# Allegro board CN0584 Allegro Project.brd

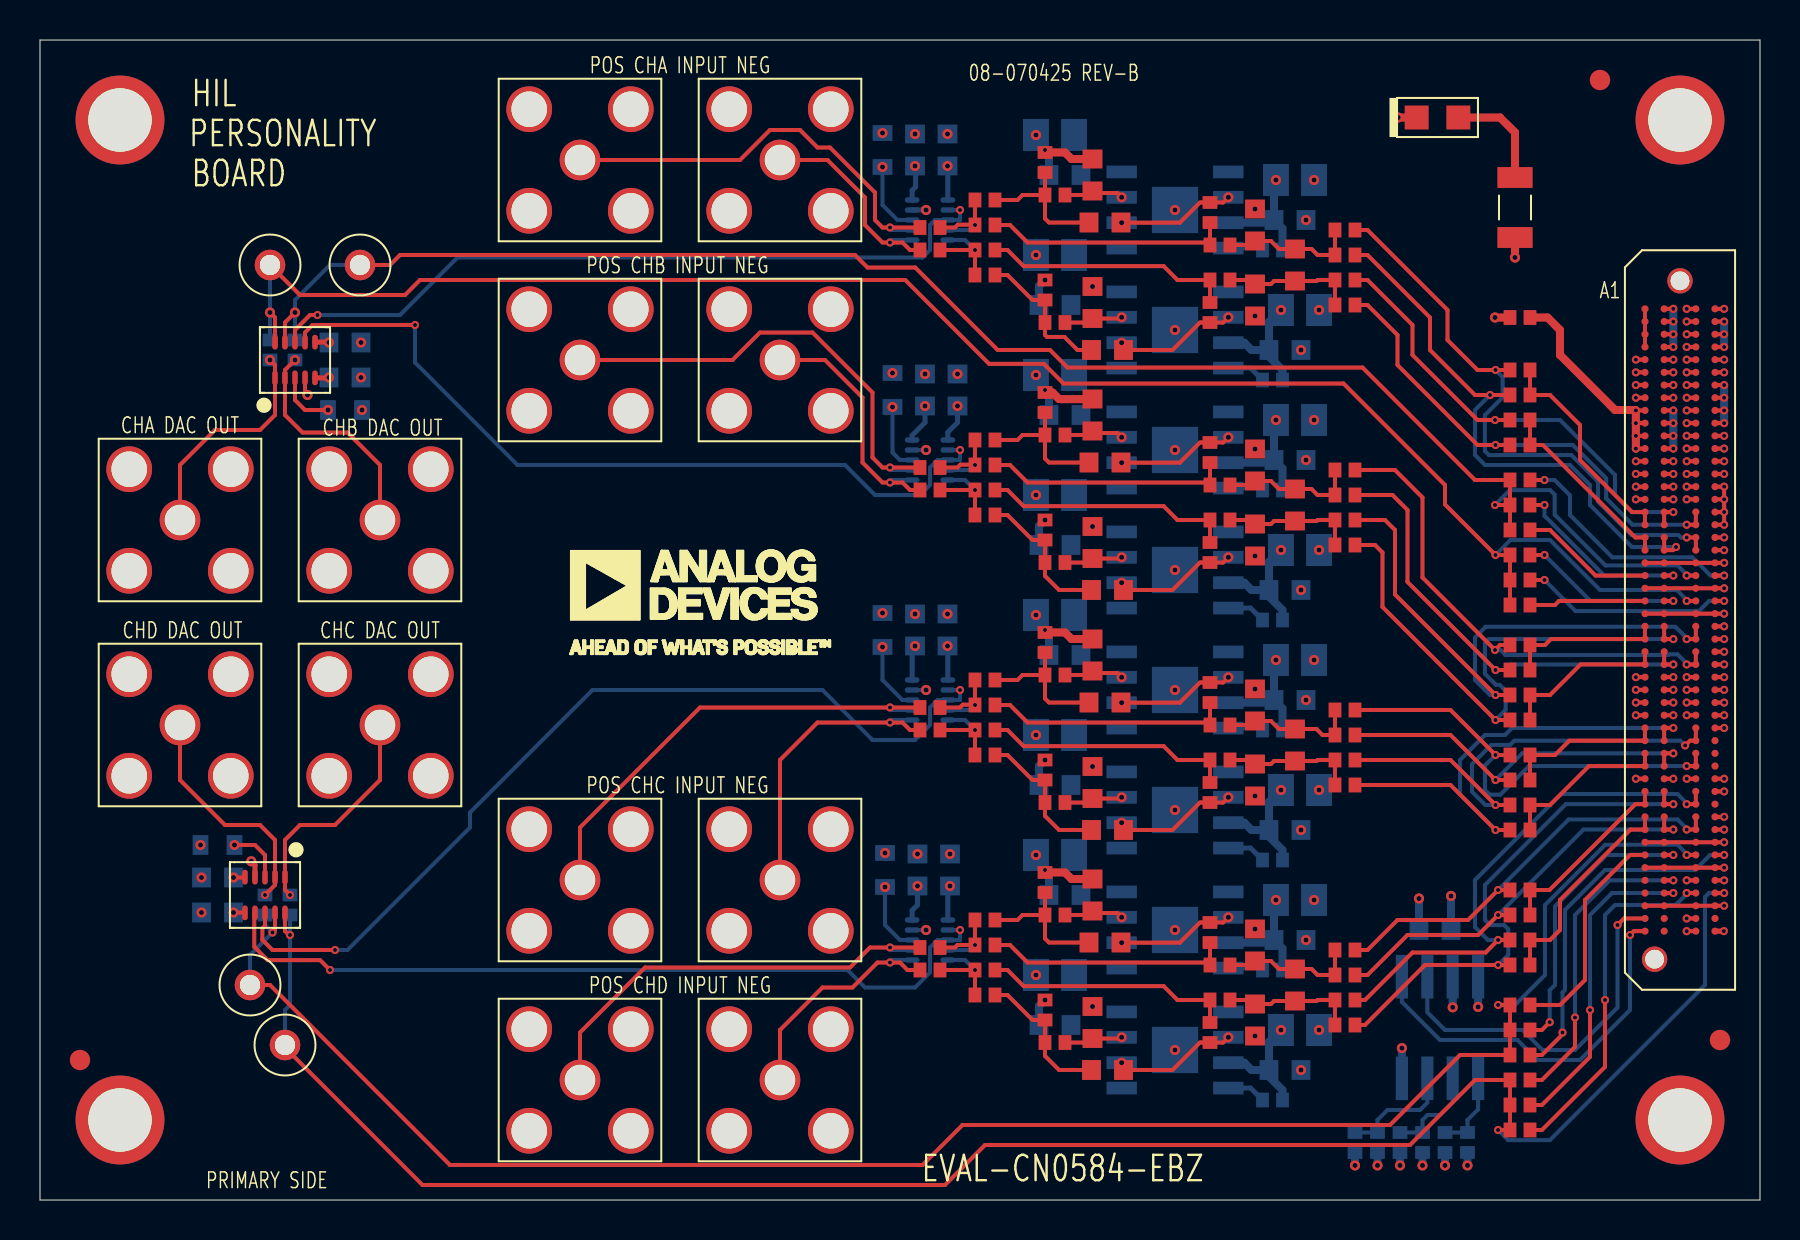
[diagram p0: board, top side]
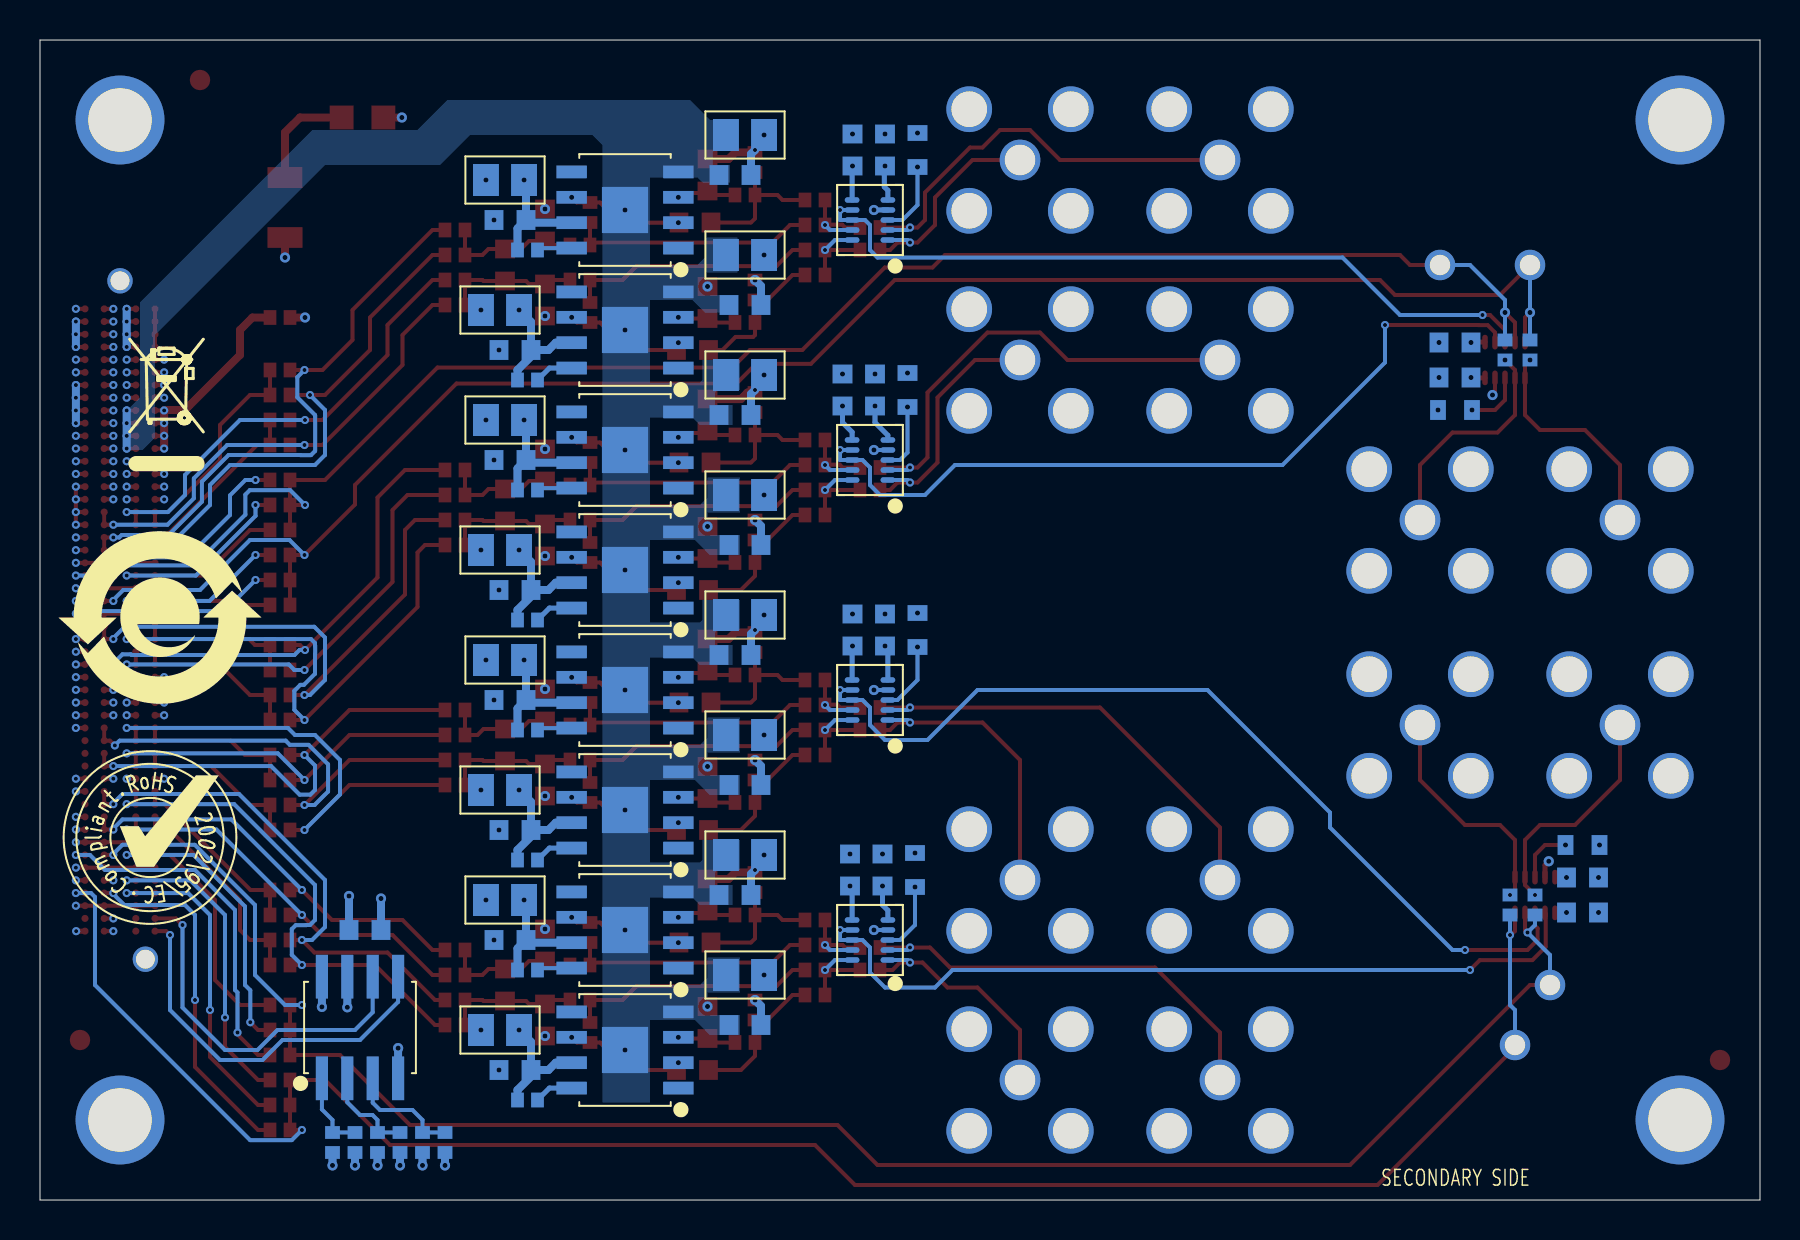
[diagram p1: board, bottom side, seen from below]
Outline 86 x 58 mm; copper layers: TOP, LAYER_2, LAYER_3, LAYER_4, LAYER_5, BOTTOM. Coordinates in mm from the lower left corner of the outline.
Outline path: 0,58 0,0 86,0 86,58 0,58

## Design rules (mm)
constraint set DEFAULT: 

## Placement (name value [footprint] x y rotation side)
C1  0.1uF  [C0603]  69.75 13.5 0 bottom
C1A  0.1uF  [C0603]  43.75 52.5 270 bottom
C1B  0.1uF  [C0603]  44.25 40.5 270 bottom
C1C  0.1uF  [C0603]  43.75 28.5 270 bottom
C1D  0.1uF  [C0603]  43.88 16.5 270 bottom
C2  0.1uF  [C0603]  8.88 16.12 0 bottom
C2A  0.1uF  [C0603]  45.38 52.5 270 bottom
C2B  0.1uF  [C0603]  45.88 40.5 270 bottom
C2C  0.1uF  [C0603]  45.38 28.5 270 bottom
C2D  0.1uF  [C0603]  45.5 16.5 270 bottom
C3  0.1uF  [C0603]  15.25 41.12 180 bottom
C3A  0.47uF  [C0603]  53.38 42.5 180 top
C3B  0.47uF  [C0603]  53.38 30.5 180 top
C3C  0.47uF  [C0603]  53.38 18.5 180 top
C3D  0.47uF  [C0603]  53.38 6.5 180 top
C4  0.1uF  [C0603]  15.25 42.88 180 bottom
C4A  0.47uF  [C0603]  53.25 48.88 180 top
C4B  0.47uF  [C0603]  53.25 36.88 180 top
C4C  0.47uF  [C0603]  53.25 24.88 180 top
C4D  0.47uF  [C0603]  53.25 12.88 180 top
C5  0.1uF  [C0603]  8.88 14.38 0 bottom
C5A  0.47uF  [C0603]  52.62 44.88 270 top
C5B  0.47uF  [C0603]  52.62 32.88 270 top
C5C  0.47uF  [C0603]  52.62 20.88 270 top
C5D  0.47uF  [C0603]  52.62 8.88 270 top
C6A  0.47uF  [C0603]  52.62 51.25 270 top
C6B  0.47uF  [C0603]  52.62 39.25 270 top
C6C  0.47uF  [C0603]  52.62 27.25 270 top
C6D  0.47uF  [C0603]  52.62 15.25 270 top
C7A  4.7uF  [C0805H53]  62.75 51 180 bottom
C7B  4.7uF  [C0805H53]  62.75 39 180 bottom
C7C  4.7uF  [C0805H53]  62.75 27 180 bottom
C7D  4.7uF  [C0805H53]  63 8.5 180 bottom
C8A  4.7uF  [C0805H53]  63 44.5 180 bottom
C8B  4.7uF  [C0805H53]  63 32.5 180 bottom
C8C  4.7uF  [C0805H53]  63 20.5 180 bottom
C8D  4.7uF  [C0805H53]  62.75 15 180 bottom
C9A  0.1uF  [C0603]  62.5 49 180 bottom
C9B  0.1uF  [C0603]  62.5 37 180 bottom
C9C  0.1uF  [C0603]  62.25 18.5 180 bottom
C9D  0.1uF  [C0603]  62.5 13 180 bottom
C10A  0.1uF  [C0603]  62.25 42.5 180 bottom
C10B  0.1uF  [C0603]  62.25 30.5 180 bottom
C10C  0.1uF  [C0603]  62.5 25 180 bottom
C10D  0.1uF  [C0603]  62.25 6.5 180 bottom
C11A  0.1uF  [C0603]  51.25 51.25 0 bottom
C11B  0.1uF  [C0603]  51.25 39.25 0 bottom
C11C  0.1uF  [C0603]  51.25 27.25 0 bottom
C11D  0.1uF  [C0603]  50.75 8.75 0 bottom
C12A  0.1uF  [C0603]  50.75 44.75 0 bottom
C12B  0.1uF  [C0603]  50.75 32.75 0 bottom
C12C  0.1uF  [C0603]  50.75 20.75 0 bottom
C12D  0.1uF  [C0603]  51.25 15.25 0 bottom
C13A  4.7uF  [C0805H53]  50.75 47.25 0 bottom
C13B  4.7uF  [C0805H53]  50.75 41.25 0 bottom
C13C  4.7uF  [C0805H53]  50.75 23.25 0 bottom
C13D  4.7uF  [C0805H53]  50.75 11.25 0 bottom
C14A  4.7uF  [C0805H53]  50.75 53.25 0 bottom
C14B  4.7uF  [C0805H53]  50.75 35.25 0 bottom
C14C  4.7uF  [C0805H53]  50.75 29.25 0 bottom
C14D  4.7uF  [C0805H53]  50.75 17.25 0 bottom
C15A  0.47uF  [C0603]  60.75 45 90 top
C15B  0.47uF  [C0603]  60.75 33 90 top
C15C  0.47uF  [C0603]  60.75 21 90 top
C15D  0.47uF  [C0603]  60.75 9 90 top
C16A  0.47uF  [C0603]  60.75 48.75 90 top
C16B  0.47uF  [C0603]  60.75 36.75 90 top
C16C  0.47uF  [C0603]  60.75 24.75 90 top
C16D  0.47uF  [C0603]  60.75 12.75 90 top
C17A  0.47uF  [C0603]  62.75 46.75 270 top
C17B  0.47uF  [C0603]  62.75 34.75 270 top
C17C  0.47uF  [C0603]  62.75 22.75 270 top
C17D  0.47uF  [C0603]  62.75 10.75 270 top
DS1  SML-LXT0805GW-TR  [LXT0805]  69.88 54.12 0 top
J1  901-144-8RFX  [CNTHSMASQ276H391]  27 52 0 top
J2  901-144-8RFX  [CNTHSMASQ276H391]  37 52 0 top
J3  901-144-8RFX  [CNTHSMASQ276H391]  27 42 0 top
J4  901-144-8RFX  [CNTHSMASQ276H391]  37 42 0 top
J5  901-144-8RFX  [CNTHSMASQ276H391]  27 16 0 top
J6  901-144-8RFX  [CNTHSMASQ276H391]  37 16 0 top
J7  901-144-8RFX  [CNTHSMASQ276H391]  27 6 0 top
J8  901-144-8RFX  [CNTHSMASQ276H391]  37 6 0 top
J9  901-144-8RFX  [CNTHSMASQ276H391]  7 34 0 top
J10  901-144-8RFX  [CNTHSMASQ276H391]  17 34 0 top
J11  901-144-8RFX  [CNTHSMASQ276H391]  17 23.75 0 top
J12  901-144-8RFX  [CNTHSMASQ276H391]  7 23.75 0 top
NOREF  -  []  26.5 26 0 top
NOREF#2  -  [unnamed#2]  2 7 0 top
NOREF#3  -  []  43 74 0 top
NOREF#4  -  []  86 58 180 top
NOREF#5  -  [unnamed#2]  4 54 0 top
NOREF#6  -  []  -67.2 -72.2 0 top
NOREF#7  -  []  -67.2 -72.2 0 top
NOREF#8  -  []  0 58 270 top
NOREF#9  -  [unnamed#2]  4 4 0 top
NOREF#10  -  []  249.66 215.46 0 top
NOREF#11  -  []  16.62 327.21 0 top
NOREF#12  -  []  0 0 0 top
NOREF#13  -  [unnamed#2]  82 54 0 top
NOREF#14  -  [unnamed#2]  84 8 0 top
NOREF#15  -  []  259.19 222.44 0 top
NOREF#16  -  []  86 0 90 top
NOREF#17  -  [unnamed#2]  82 4 0 top
NOREF#18  -  [unnamed#2]  78 56 0 top
NOREF#19  -  []  -67.2 -72.2 0 top
NOREF#20  -  []  80.5 18.12 180 bottom
NOREF#21  -  []  79.88 36.5 180 bottom
NOREF#22  -  []  80 29.12 180 bottom
P1  ADM6-50-01.5-L-4-2-A-TR  [CNSMMHDR4X50L1436W197H161]  82 29 270 top
R1  560  [R1206]  73.75 49.62 90 top
R1A  34K  [R0603]  42.12 52.5 90 bottom
R1B  34K  [R0603]  42.62 40.5 90 bottom
R1C  34K  [R0603]  42.12 28.5 90 bottom
R1D  34K  [R0603]  42.25 16.5 90 bottom
R2  0  [R0402]  74 44.12 0 top
R2A  0  [R0402]  44.5 47.5 0 top
R2B  0  [R0402]  44.5 35.5 0 top
R2C  0  [R0402]  44.5 23.5 0 top
R2D  0  [R0402]  44.5 11.5 0 top
R3  0  [R0402]  70.25 2.88 90 bottom
R3A  0  [R0402]  44.5 48.62 0 top
R3B  0  [R0402]  44.5 36.62 0 top
R3C  0  [R0402]  44.5 24.62 0 top
R3D  0  [R0402]  44.5 12.62 0 top
R4  10K  [R0402]  71.38 2.88 90 bottom
R4A  1K  [R0402]  47.25 46.25 0 top
R4B  1K  [R0402]  47.25 34.25 0 top
R4C  1K  [R0402]  47.25 22.25 0 top
R4D  1K  [R0402]  47.25 10.25 0 top
R5  0  [R0402]  68 2.88 90 bottom
R5A  1K  [R0402]  47.25 50 180 top
R5B  1K  [R0402]  47.25 38 180 top
R5C  1K  [R0402]  47.25 26 180 top
R5D  1K  [R0402]  47.25 14 180 top
R6  10K  [R0402]  69.12 2.88 90 bottom
R6A  10K  [R0402]  50.25 45.5 270 top
R6B  10K  [R0402]  50.25 33.5 270 top
R6C  10K  [R0402]  50.25 21.5 270 top
R6D  10K  [R0402]  50.25 9.5 270 top
R7  0  [R0402]  65.75 2.88 90 bottom
R7A  10K  [R0402]  50.25 51.88 270 top
R7B  10K  [R0402]  50.25 39.88 270 top
R7C  10K  [R0402]  50.25 27.88 270 top
R7D  10K  [R0402]  50.25 15.88 270 top
R8  10K  [R0402]  66.88 2.88 90 bottom
R8A  0  [R0402]  50.75 43.88 0 top
R8B  0  [R0402]  50.75 31.88 0 top
R8C  0  [R0402]  50.75 19.88 0 top
R8D  0  [R0402]  50.75 7.88 0 top
R9  0  [R0402]  74 31 0 top
R9A  0  [R0402]  50.75 50.25 0 top
R9B  0  [R0402]  50.75 38.25 0 top
R9C  0  [R0402]  50.75 26.25 0 top
R9D  0  [R0402]  50.75 14.25 0 top
R10  0  [R0402]  74 29.75 0 top
R10A  0  [R0402]  47.25 47.5 0 top
R10B  0  [R0402]  47.25 35.5 0 top
R10C  0  [R0402]  47.25 23.5 0 top
R10D  0  [R0402]  47.25 11.5 0 top
R11  0  [R0402]  74 32.25 0 top
R11A  0  [R0402]  47.25 48.75 0 top
R11B  0  [R0402]  47.25 36.75 0 top
R11C  0  [R0402]  47.25 24.75 0 top
R11D  0  [R0402]  47.25 12.75 0 top
R12  0  [R0402]  74 36 0 top
R12A  0  [R0402]  61.62 47.5 180 bottom
R12B  0  [R0402]  61.62 35.5 180 bottom
R12C  0  [R0402]  61.62 23.5 180 bottom
R12D  0  [R0402]  61.62 11.5 180 bottom
R13  0  [R0402]  74 34.75 0 top
R13A  0  [R0402]  61.62 41 180 bottom
R13B  0  [R0402]  61.62 29 180 bottom
R13C  0  [R0402]  61.62 17 180 bottom
R13D  0  [R0402]  61.62 5 180 bottom
R14  0  [R0402]  74 33.5 0 top
R14A  0  [R0402]  58.5 44.38 270 top
R14B  0  [R0402]  58.5 32.38 270 top
R14C  0  [R0402]  58.5 20.38 270 top
R14D  0  [R0402]  58.5 8.38 270 top
R15  0  [R0402]  74 6 0 top
R15A  0  [R0402]  58.5 49.38 270 top
R15B  0  [R0402]  58.5 37.38 270 top
R15C  0  [R0402]  58.5 25.38 270 top
R15D  0  [R0402]  58.5 13.38 270 top
R16  0  [R0402]  74 3.5 0 top
R16A  0  [R0402]  59 46 180 top
R16B  0  [R0402]  59 34 180 top
R16C  0  [R0402]  59 22 180 top
R16D  0  [R0402]  59 10 180 top
R17  0  [R0402]  74 4.75 0 top
R17A  0  [R0402]  59 47.75 180 top
R17B  0  [R0402]  59 35.75 180 top
R17C  0  [R0402]  59 23.75 180 top
R17D  0  [R0402]  59 11.75 180 top
R18  0  [R0402]  74 7.25 0 top
R18A  0  [R0402]  65.25 46 180 top
R18B  0  [R0402]  65.25 32.75 180 top
R18C  0  [R0402]  65.25 20.75 180 top
R18D  0  [R0402]  65.25 8.75 180 top
R19  0  [R0402]  74 8.5 0 top
R19A  0  [R0402]  65.25 44.75 180 top
R19B  0  [R0402]  65.25 34 180 top
R19C  0  [R0402]  65.25 22 180 top
R19D  0  [R0402]  65.25 10 180 top
R20  0  [R0402]  74 9.75 0 top
R20A  0  [R0402]  65.25 47.25 180 top
R20B  0  [R0402]  65.25 35.25 180 top
R20C  0  [R0402]  65.25 23.25 180 top
R20D  0  [R0402]  65.25 11.25 180 top
R21  34K  [R0603]  8.88 17.75 180 bottom
R21A  0  [R0402]  65.25 48.5 180 top
R21B  0  [R0402]  65.25 36.5 180 top
R21C  0  [R0402]  65.25 24.5 180 top
R21D  0  [R0402]  65.25 12.5 180 top
R22  34K  [R0603]  15.25 39.5 0 bottom
R22A  0  [R0402]  74 39 180 top
R22B  0  [R0402]  74 24 180 top
R22C  0  [R0402]  74 18.5 180 top
R22D  0  [R0402]  74 11.75 180 top
R23  0  [R0402]  11.5 42.5 90 bottom
R23A  0  [R0402]  74 37.75 180 top
R23B  0  [R0402]  74 25.25 180 top
R23C  0  [R0402]  74 19.75 180 top
R23D  0  [R0402]  74 13 180 top
R24  0  [R0402]  12.5 14.75 270 bottom
R24A  0  [R0402]  74 40.25 180 top
R24B  0  [R0402]  74 26.5 180 top
R24C  0  [R0402]  74 21 180 top
R24D  0  [R0402]  74 14.25 180 top
R25  0  [R0402]  12.75 42.5 90 bottom
R25A  0  [R0402]  74 41.5 180 top
R25B  0  [R0402]  74 27.75 180 top
R25C  0  [R0402]  74 22.25 180 top
R25D  0  [R0402]  74 15.5 180 top
R26  0  [R0402]  11.25 14.75 270 bottom
TP1  BLK  [CNKEY5001TP]  11.5 46.75 90 top
TP2  BLK  [CNKEY5001TP]  16 46.75 90 top
TP3  BLK  [CNKEY5001TP]  12.25 7.75 270 top
TP4  BLK  [CNKEY5001TP]  10.5 10.75 270 top
U1  M24C02-RMN6TP  [SO8]  70 8.62 180 bottom
U1A  ADG5421FBCPZ-RL7  [DFN10_3X2]  44.5 49 90 bottom
U1B  ADG5421FBCPZ-RL7  [DFN10_3X2]  44.5 37 90 bottom
U1C  ADG5421FBCPZ-RL7  [DFN10_3X2]  44.5 25 90 bottom
U1D  ADG5421FBCPZ-RL7  [DFN10_3X2]  44.5 13 90 bottom
U2  ADG5421FBCPZ-RL7  [DFN10_3X2]  12.75 42 0 top
U2A  ADA4898-1YRDZ  [SO8NB-PAD2_3X2_3]  56.75 49.5 90 bottom
U2B  ADA4898-1YRDZ  [SO8NB-PAD2_3X2_3]  56.75 37.5 90 bottom
U2C  ADA4898-1YRDZ  [SO8NB-PAD2_3X2_3]  56.75 25.5 90 bottom
U2D  ADA4898-1YRDZ  [SO8NB-PAD2_3X2_3]  56.75 13.5 90 bottom
U3  ADG5421FBCPZ-RL7  [DFN10_3X2]  11.25 15.25 180 top
U3A  ADA4898-1YRDZ  [SO8NB-PAD2_3X2_3]  56.75 43.5 90 bottom
U3B  ADA4898-1YRDZ  [SO8NB-PAD2_3X2_3]  56.75 31.5 90 bottom
U3C  ADA4898-1YRDZ  [SO8NB-PAD2_3X2_3]  56.75 19.5 90 bottom
U3D  ADA4898-1YRDZ  [SO8NB-PAD2_3X2_3]  56.75 7.5 90 bottom

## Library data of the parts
C1 C1A C1B C1C C1D C2 C2A C2B C2C C2D C3-C5 C9A C9B C9C C9D C10A C10B C10C C10D C11A C11B C11C C11D C12A C12B C12C C12D = CAP: User Part Number: UPN; Tolerance: 10; alternate symbols: (C0603L); part number: CAP_SM-0.1UF,50V,10,E011865,C0603; tolerance: 10
C3A C3B C3C C3D C4A C4B C4C C4D C5A C5B C5C C5D C6A C6B C6C C6D C15A C15B C15C C15D C16A C16B C16C C16D C17A C17B C17C C17D = CAP: User Part Number: UPN; Tolerance: 10; alternate symbols: (C0603L); part number: CAP_SM-0.47UF,16V,10,E012085,C0603; tolerance: 10
C7A C7B C7C C7D C8A C8B C8C C8D C13A C13B C13C C13D C14A C14B C14C C14D = CAP: Tolerance: 10; User Part Number: UPN; alternate symbols: (); part number: CAP_SM-4.7UF,50V,10,E028468,C0805H53; tolerance: 10
DS1 = DIOLED: Tolerance: N/A; User Part Number: UPN; alternate symbols: (); part number: DIOLED_SM-SML-LXT0805GW-TR,N/A,N/A,E005318,LXT0805; tolerance: N/A
J1-J12 = CNBNC5P: Tolerance: N/A; User Part Number: UPN; alternate symbols: (); part number: CNBNC5P_TH-901-144-8RFX,E013428,CNTHSMASQ276H391; tolerance: N/A
P1 = CN200P_ABCD: User Part Number: UPN; Tolerance: N/A; alternate symbols: (); part number: CN200P_ABCD_SM-ADM6-50-01.5-L-4-2-A-TR,E056353,CNSMMHDR4X50L1436W197H161; tolerance: N/A
R1 = RES: User Part Number: UPN; Tolerance: 1; alternate symbols: (R1206L); part number: RES_SM-560,E012728,1/4W,1,R1206; tolerance: 1
R1A R1B R1C R1D R21 R22 = RES: User Part Number: UPN; Tolerance: 1; alternate symbols: (R0603L); part number: RES_SM-34K,E003688,1/10W,1,R0603; tolerance: 1
R2 R2A R2B R2C R2D R3 R3A R3B R3C R3D R5 R7 R8A R8B R8C R8D R9 R9A R9B R9C R9D R10 R10A R10B R10C R10D R11 R11A R11B R11C R11D R12 R12A R12B R12C R12D R13 R13A R13B R13C R13D R14 R14A R14B R14C R14D R15 R15A R15B R15C R15D R16 R16A R16B R16C R16D R17 R17A R17B R17C R17D R18 R18A R18B R18C R18D R19 R19A R19B R19C R19D R20 R20A R20B R20C R20D R21A R21B R21C R21D R22A R22B R22C R22D R23 R23A R23B R23C R23D R24 R24A R24B R24C R24D R25 R25A R25B R25C R25D R26 = RES: User Part Number: UPN; Tolerance: JUMPER; alternate symbols: (R0402L,R0402L_ALT); part number: RES_SM-0,E003438,1/10W,JUMPER,R0402; tolerance: JUMPER
R4 R6 R6A R6B R6C R6D R7A R7B R7C R7D R8 = RES: User Part Number: UPN; Tolerance: 1; alternate symbols: (R0402L,R0402L_ALT); part number: RES_SM-10K,E003751,1/10W,1,R0402; tolerance: 1
R4A R4B R4C R4D R5A R5B R5C R5D = RES: User Part Number: UPN; Tolerance: 5; alternate symbols: (R0402L); part number: RES_SM-1K,E020936,1/16W,5,R0402; tolerance: 5
TP1-TP4 = CNTP1P: Tolerance: N/A; User Part Number: UPN; alternate symbols: (); part number: CNTP1P_TH-BLK,E005347,CNKEY5001TP; tolerance: N/A
U1 = ICM24CXX: Tolerance: N/A; User Part Number: UPN; alternate symbols: (); part number: ICM24CXX_SM-M24C02-RMN6TP,E018349,SO8; tolerance: N/A
U1A U1B U1C U1D U2 U3 = ADG5421F: User Part Number: UPN; Tolerance: N/A; alternate symbols: (); part number: ADG5421F_SM-ADG5421FBCPZ-RL7,E033675,DFN10_3X2; tolerance: N/A
U2A U2B U2C U2D U3A U3B U3C U3D = ADA4898: Tolerance: N/A; User Part Number: UPN; alternate symbols: (); part number: ADA4898_SM-ADA4898-1YRDZ,E010180,SO8NB-PAD2_3X2_3; tolerance: N/A

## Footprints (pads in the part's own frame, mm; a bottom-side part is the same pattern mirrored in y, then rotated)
C0603
  rect 0.94x0.991 smd: 1(-0.8,0) 2(0.8,0)
C0805H53
  rect 1.295x1.6 smd: 1(-0.953,0) 2(0.953,0)
CNKEY5001TP
  round 1.524 hole 1.016: 1(0,0)
CNSMMHDR4X50L1436W197H161
  round 1.27 hole 0.94 unplated: (-16.96,0) (16.96,-1.27)
  round 0.356 smd: A1(-15.557,-1.75) A2(-14.922,-1.75) A3(-14.287,-1.75) A4(-13.652,-1.75) A5(-13.018,-1.75) A6(-12.383,-1.75) A7(-11.748,-1.75) A8(-11.113,-1.75) A9(-10.477,-1.75) A10(-9.842,-1.75) A11(-9.207,-1.75) A12(-8.572,-1.75) A13(-7.938,-1.75) A14(-7.303,-1.75) A15(-6.668,-1.75) A16(-6.032,-1.75) A17(-5.397,-1.75) A18(-4.763,-1.75) A19(-4.128,-1.75) A20(-3.493,-1.75) A21(-2.857,-1.75) A22(-2.223,-1.75) A23(-1.587,-1.75) A24(-0.953,-1.75) A25(-0.318,-1.75) A26(0.318,-1.75) A27(0.953,-1.75) A28(1.587,-1.75) A29(2.223,-1.75) A30(2.857,-1.75) A31(3.493,-1.75) A32(4.128,-1.75) A33(4.763,-1.75) A34(5.397,-1.75) A35(6.032,-1.75) A36(6.668,-1.75) A37(7.303,-1.75) A38(7.938,-1.75) A39(8.572,-1.75) A40(9.207,-1.75) A41(9.842,-1.75) A42(10.477,-1.75) A43(11.113,-1.75) A44(11.748,-1.75) A45(12.383,-1.75) A46(13.018,-1.75) A47(13.652,-1.75) A48(14.287,-1.75) A49(14.922,-1.75) A50(15.557,-1.75) B1(-15.557,-0.79) B2(-14.922,-0.79) B3(-14.287,-0.79) B4(-13.652,-0.79) B5(-13.018,-0.79) B6(-12.383,-0.79) B7(-11.748,-0.79) B8(-11.113,-0.79) B9(-10.477,-0.79) B10(-9.842,-0.79) B11(-9.207,-0.79) B12(-8.572,-0.79) B13(-7.938,-0.79) B14(-7.303,-0.79) B15(-6.668,-0.79) B16(-6.032,-0.79) B17(-5.397,-0.79) B18(-4.763,-0.79) B19(-4.128,-0.79) B20(-3.493,-0.79) B21(-2.857,-0.79) B22(-2.223,-0.79) B23(-1.587,-0.79) B24(-0.953,-0.79) B25(-0.318,-0.79) B26(0.318,-0.79) B27(0.953,-0.79) B28(1.587,-0.79) B29(2.223,-0.79) B30(2.857,-0.79) B31(3.493,-0.79) B32(4.128,-0.79) B33(4.763,-0.79) B34(5.397,-0.79) B35(6.032,-0.79) B36(6.668,-0.79) B37(7.303,-0.79) B38(7.938,-0.79) B39(8.572,-0.79) B40(9.207,-0.79) B41(9.842,-0.79) B42(10.477,-0.79) B43(11.113,-0.79) B44(11.748,-0.79) B45(12.383,-0.79) B46(13.018,-0.79) B47(13.652,-0.79) B48(14.287,-0.79) B49(14.922,-0.79) B50(15.557,-0.79) C1(-15.557,0.79) C2(-14.922,0.79) C3(-14.287,0.79) C4(-13.652,0.79) C5(-13.018,0.79) C6(-12.383,0.79) C7(-11.748,0.79) C8(-11.113,0.79) C9(-10.477,0.79) C10(-9.842,0.79) C11(-9.207,0.79) C12(-8.572,0.79) C13(-7.938,0.79) C14(-7.303,0.79) C15(-6.668,0.79) C16(-6.032,0.79) C17(-5.397,0.79) C18(-4.763,0.79) C19(-4.128,0.79) C20(-3.493,0.79) C21(-2.857,0.79) C22(-2.223,0.79) C23(-1.587,0.79) C24(-0.953,0.79) C25(-0.318,0.79) C26(0.318,0.79) C27(0.953,0.79) C28(1.587,0.79) C29(2.223,0.79) C30(2.857,0.79) C31(3.493,0.79) C32(4.128,0.79) C33(4.763,0.79) C34(5.397,0.79) C35(6.032,0.79) C36(6.668,0.79) C37(7.303,0.79) C38(7.938,0.79) C39(8.572,0.79) C40(9.207,0.79) C41(9.842,0.79) C42(10.477,0.79) C43(11.113,0.79) C44(11.748,0.79) C45(12.383,0.79) C46(13.018,0.79) C47(13.652,0.79) C48(14.287,0.79) C49(14.922,0.79) C50(15.557,0.79) D1(-15.557,1.75) D2(-14.922,1.75) D3(-14.287,1.75) D4(-13.652,1.75) D5(-13.018,1.75) D6(-12.383,1.75) D7(-11.748,1.75) D8(-11.113,1.75) D9(-10.477,1.75) D10(-9.842,1.75) D11(-9.207,1.75) D12(-8.572,1.75) D13(-7.938,1.75) D14(-7.303,1.75) D15(-6.668,1.75) D16(-6.032,1.75) D17(-5.397,1.75) D18(-4.763,1.75) D19(-4.128,1.75) D20(-3.493,1.75) D21(-2.857,1.75) D22(-2.223,1.75) D23(-1.587,1.75) D24(-0.953,1.75) D25(-0.318,1.75) D26(0.318,1.75) D27(0.953,1.75) D28(1.587,1.75) D29(2.223,1.75) D30(2.857,1.75) D31(3.493,1.75) D32(4.128,1.75) D33(4.763,1.75) D34(5.397,1.75) D35(6.032,1.75) D36(6.668,1.75) D37(7.303,1.75) D38(7.938,1.75) D39(8.572,1.75) D40(9.207,1.75) D41(9.842,1.75) D42(10.477,1.75) D43(11.113,1.75) D44(11.748,1.75) D45(12.383,1.75) D46(13.018,1.75) D47(13.652,1.75) D48(14.287,1.75) D49(14.922,1.75) D50(15.557,1.75)
CNTHSMASQ276H391
  round 2.032 hole 1.524: 1(0,0)
  round 2.286 hole 1.778: 2(-2.54,2.54) 3(2.54,2.54) 4(2.54,-2.54) 5(-2.54,-2.54)
DFN10_3X2
  oval 0.279x0.737 smd: 1(-1,-0.893) 2(-0.5,-0.893) 3(0,-0.893) 4(0.5,-0.893) 5(1,-0.893) 6(1,0.893) 7(0.5,0.893) 8(0,0.893) 9(-0.5,0.893) 10(-1,0.893)
LXT0805
  rect 1.194x1.194 smd: A(1.041,0) C(-1.041,0)
R0402
  rect 0.635x0.737 smd: 1(-0.5,0) 2(0.5,0)
R0603
  rect 0.787x0.991 smd: 1(-0.85,0) 2(0.85,0)
R1206
  rect 1.041x1.753 smd: 1(-1.5,0) 2(1.5,0)
SO8
  rect 0.61x2.184 smd: 1(-1.905,-2.54) 2(-0.635,-2.54) 3(0.635,-2.54) 4(1.905,-2.54) 5(1.905,2.54) 6(0.635,2.54) 7(-0.635,2.54) 8(-1.905,2.54)
SO8NB-PAD2_3X2_3
  rect 0.635x1.524 smd: 1(-1.905,-2.667) 2(-0.635,-2.667) 3(0.635,-2.667) 4(1.905,-2.667) 5(1.905,2.667) 6(0.635,2.667) 7(-0.635,2.667) 8(-1.905,2.667)
  rect 2.311x2.311 smd: PAD(0,0)
unnamed#2
  round 1.016 smd: (0,0)

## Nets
3V3_EEPROM: C1.2(N2) P1.C12 P1.C13 R3.1 R5.1 R7.1 U1.8
+12V: C7A.2(N2) C7B.2(N2) C7C.2(N2) C7D.2(N2) C8A.2(N2) C8B.2(N2) C8C.2(N2) C8D.2(N2) C9A.2(N2) C9B.2(N2) C9C.2(N2) C9D.2(N2) C10A.2(N2) C10B.2(N2) C10C.2(N2) C10D.2(N2) P1.B1 P1.B2 P1.B3 P1.B4 R1.1 R12A.1 R12B.1 R12C.1 R12D.1 R13A.1 R13B.1 R13C.1 R13D.1 U2A.7(VS_POS) U2B.7(VS_POS) U2C.7(VS_POS) U2D.7(VS_POS) U3A.7(VS_POS) U3B.7(VS_POS) U3C.7(VS_POS) U3D.7(VS_POS)
+12V-40V: P1.A1 P1.A2 P1.A3 P1.A4
+15V: C1A.2(N2) C1B.2(N2) C1C.2(N2) C1D.2(N2) C2.2(N2) C3.2(N2) P1.D1 P1.D2 P1.D3 P1.D4 U1A.5 U1B.5 U1C.5 U1D.5 U2.5 U3.5
-12V: C11A.2(N2) C11B.2(N2) C11C.2(N2) C11D.2(N2) C12A.2(N2) C12B.2(N2) C12C.2(N2) C12D.2(N2) C13A.2(N2) C13B.2(N2) C13C.2(N2) C13D.2(N2) C14A.2(N2) C14B.2(N2) C14C.2(N2) C14D.2(N2) P1.B9 P1.B10 P1.B11 P1.B12 U2A.4 U2A.PAD U2B.4 U2B.PAD U2C.4 U2C.PAD U2D.4 U2D.PAD U3A.4 U3A.PAD U3B.4 U3B.PAD U3C.4 U3C.PAD U3D.4 U3D.PAD
-15V: C2A.2(N2) C2B.2(N2) C2C.2(N2) C2D.2(N2) C4.2(N2) C5.2(N2) P1.D7 P1.D8 P1.D9(N9) P1.D10 U1A.6(VSS) U1B.6(VSS) U1C.6(VSS) U1D.6(VSS) U2.6(VSS) U3.6(VSS)
3P3V: P1.A9 P1.A10 P1.A11 P1.A12 R2.2(N2)
ADC0_IN1N: P1.B19 P1.B20 R20A.1 R24A.2(N2)
ADC0_IN1P: P1.B17 P1.B18 R18A.1 R22A.2(N2)
ADC0_IN2N: P1.C19 P1.C20 R21A.1 R25A.2(N2)
ADC0_IN2P: P1.C17 P1.C18 R19A.1 R23A.2(N2)
ADC0_OUTN: P1.A19 P1.A20 R22A.1 R23A.1
ADC0_OUTP: P1.A17 P1.A18 R24A.1 R25A.1
ADC1_IN1N: P1.B28 P1.B29 R20B.1 R24B.2(N2)
ADC1_IN1P: P1.B26 P1.B27 R18B.1 R22B.2(N2)
ADC1_IN2N: P1.C28 P1.C29 R21B.1 R25B.2(N2)
ADC1_IN2P: P1.C26 P1.C27 R19B.1 R23B.2(N2)
ADC1_OUTN: P1.A28 P1.A29 R22B.1 R23B.1
ADC1_OUTP: P1.A26 P1.A27 R24B.1 R25B.1
ADC2_IN1N: P1.B36 P1.B37 R20C.1 R24C.2(N2)
ADC2_IN1P: P1.B34 P1.B35 R18C.1 R22C.2(N2)
ADC2_IN2N: P1.C36 P1.C37 R21C.1 R25C.2(N2)
ADC2_IN2P: P1.C34 P1.C35 R19C.1 R23C.2(N2)
ADC2_OUTN: P1.A36 P1.A37 R22C.1 R23C.1
ADC2_OUTP: P1.A34 P1.A35 R24C.1 R25C.1
ADC3_IN1N: P1.B41 P1.B42 R20D.1 R24D.2(N2)
ADC3_IN1P: P1.B39 P1.B40 R18D.1 R22D.2(N2)
ADC3_IN2N: P1.C41 P1.C42 R21D.1 R25D.2(N2)
ADC3_IN2P: P1.C39 P1.C40 R19D.1 R23D.2(N2)
ADC3_OUTN: P1.A41 P1.A42 R22D.1 R23D.1
ADC3_OUTP: P1.A39 P1.A40 R24D.1 R25D.1
CHA_N: J2.1 R2A.1 U1A.1
CHA_P: J1.1 R3A.1 U1A.2
CHB_N: J4.1 R2B.1 U1B.1
CHB_P: J3.1 R3B.1 U1B.2
CHC_N: J6.1 R2C.1 U1C.1
CHC_P: J5.1 R3C.1 U1C.2
CHD_N: J8.1 R2D.1 U1D.1
CHD_P: J7.1 R3D.1 U1D.2
DAC0: P1.C24 R9.1 R10.1 R11.1 R23.2(N2) TP1.1(N1) U2.10
DAC0_RFB0: P1.D24 R9.2(N2)
DAC0_RFB0_X1: P1.A24 R10.2(N2)
DAC0_RFB0_X2: P1.B24 R11.2(N2)
DAC1: P1.C22 R12.1 R13.1 R14.1 R25.2(N2) TP2.1(N1) U2.9
DAC1_RFB1: P1.D22 R12.2(N2)
DAC1_RFB1_X1: P1.A22 R14.2(N2)
DAC1_RFB1_X2: P1.B22 R13.2(N2)
DAC2: P1.D47 R15.1 R16.1 R17.1 R24.2(N2) TP3.1(N1) U3.10
DAC2_RFB0: P1.B46 R15.2(N2)
DAC2_RFB0_X1: P1.B47 R17.2(N2)
DAC2_RFB0_X2: P1.C47 R16.2(N2)
DAC3: P1.C44 R18.1 R19.1 R20.1 R26.2(N2) TP4.1(N1) U3.9
DAC3_RFB1: P1.D44 R18.2(N2)
DAC3_RFB1_X1: P1.A44 R20.2(N2)
DAC3_RFB1_X2: P1.B44 R19.2(N2)
FMC_LA14_N: P1.B50
FMC_LA14_P: P1.B49
FMC_LA31_N: P1.A46
FMC_LA31_P: P1.A47
GPIO0_VIO: P1.A31 U1A.7 U1A.8 U2.8
GPIO1_VIO: P1.B31 U1B.7 U1B.8 U2.7
GPIO2_VIO: P1.C31 U1C.7 U1C.8 U3.8
GPIO3_VIO: P1.D31 U1D.7 U1D.8 U3.7
GPIO4_VIO: P1.D42 R1A.1 R1B.1 R22.1 U1A.3 U1B.3 U2.3
GPIO5_VIO: P1.D41 R1C.1 R1D.1 R21.1 U1C.3 U1D.3 U3.3
GPIO6_VIO: P1.D40
GPIO7_VIO: P1.C49
GROUND: C1.1 C1A.1 C1B.1 C1C.1 C1D.1 C2.1 C2A.1 C2B.1 C2C.1 C2D.1 C3.1 C4.1 C5.1 C5A.1 C5B.1 C5C.1 C5D.1 C6A.1 C6B.1 C6C.1 C6D.1 C7A.1 C7B.1 C7C.1 C7D.1 C8A.1 C8B.1 C8C.1 C8D.1 C9A.1 C9B.1 C9C.1 C9D.1 C10A.1 C10B.1 C10C.1 C10D.1 C11A.1 C11B.1 C11C.1 C11D.1 C12A.1 C12B.1 C12C.1 C12D.1 C13A.1 C13B.1 C13C.1 C13D.1 C14A.1 C14B.1 C14C.1 C14D.1 C15A.1 C15B.1 C15C.1 C15D.1 C16A.2(N2) C16B.2(N2) C16C.2(N2) C16D.2(N2) DS1.C J1.2 J1.3 J1.4 J1.5(SH4) J2.2 J2.3 J2.4 J2.5(SH4) J3.2 J3.3 J3.4 J3.5(SH4) J4.2 J4.3 J4.4 J4.5(SH4) J5.2 J5.3 J5.4 J5.5(SH4) J6.2 J6.3 J6.4 J6.5(SH4) J7.2 J7.3 J7.4 J7.5(SH4) J8.2 J8.3 J8.4 J8.5(SH4) J9.2 J9.3 J9.4 J9.5(SH4) J10.2 J10.3 J10.4 J10.5(SH4) J11.2 J11.3 J11.4 J11.5(SH4) J12.2 J12.3 J12.4 J12.5(SH4) P1.A5 P1.A6 P1.A7 P1.A8 P1.A13 P1.A14 P1.A15 P1.A16 P1.A21 P1.A23 P1.A25 P1.A30 P1.A32 P1.A33 P1.A38 P1.A43 P1.A45 P1.A48 P1.B5 P1.B6 P1.B7 P1.B8 P1.B13 P1.B14 P1.B15 P1.B16 P1.B21 P1.B23 P1.B25 P1.B30 P1.B32 P1.B33 P1.B38 P1.B43 P1.B45 P1.B48 P1.C3 P1.C4 P1.C5 P1.C6 P1.C7 P1.C8 P1.C9 P1.C10 P1.C11 P1.C14 P1.C15 P1.C16 P1.C21 P1.C23 P1.C25 P1.C30 P1.C32 P1.C33 P1.C38 P1.C43 P1.C45 P1.C46 P1.C48 P1.C50 P1.D5 P1.D6 P1.D11 P1.D12 P1.D13 P1.D14 P1.D19 P1.D20 P1.D21 P1.D23 P1.D25 P1.D26 P1.D27 P1.D28 P1.D29 P1.D30 P1.D32 P1.D33 P1.D34 P1.D38 P1.D39 P1.D43 P1.D45 P1.D46 P1.D48 P1.D50 R4.1 R6.1 R6A.1 R6B.1 R6C.1 R6D.1 R7A.1 R7B.1 R7C.1 R7D.1 R8.1 U1.4 U1.7(WC_N) U1A.4 U1B.4 U1C.4 U1D.4 U2.4 U3.4
SCL: P1.A49 U1.6
SDA: P1.A50 U1.5
SPI0_CS1: P1.D49
SPI0_MISO: P1.D37
SPI0_MOSI: P1.D36
SPI0_SCK: P1.D35
UNNAMED_1_ADA4898_I21_INVA: C3A.1 R14A.2(N2) U3A.2 U3A.6
UNNAMED_1_ADA4898_I21_INVB: C3B.1 R14B.2(N2) U3B.2 U3B.6
UNNAMED_1_ADA4898_I21_INVC: C3C.1 R14C.2(N2) U3C.2 U3C.6
UNNAMED_1_ADA4898_I21_INVD: C3D.1 R14D.2(N2) U3D.2 U3D.6
UNNAMED_1_ADA4898_I21_NINVA: C5A.2(N2) R8A.2(N2) U3A.3
UNNAMED_1_ADA4898_I21_NINVB: C5B.2(N2) R8B.2(N2) U3B.3
UNNAMED_1_ADA4898_I21_NINVC: C5C.2(N2) R8C.2(N2) U3C.3
UNNAMED_1_ADA4898_I21_NINVD: C5D.2(N2) R8D.2(N2) U3D.3
UNNAMED_1_ADA4898_I21_PDNA: R13A.2(N2) U3A.8
UNNAMED_1_ADA4898_I21_PDNB: R13B.2(N2) U3B.8
UNNAMED_1_ADA4898_I21_PDNC: R13C.2(N2) U3C.8
UNNAMED_1_ADA4898_I21_PDND: R13D.2(N2) U3D.8
UNNAMED_1_ADA4898_I40_INVA: C4A.1 R15A.1 U2A.2 U2A.6
UNNAMED_1_ADA4898_I40_INVB: C4B.1 R15B.1 U2B.2 U2B.6
UNNAMED_1_ADA4898_I40_INVC: C4C.1 R15C.1 U2C.2 U2C.6
UNNAMED_1_ADA4898_I40_INVD: C4D.1 R15D.1 U2D.2 U2D.6
UNNAMED_1_ADA4898_I40_NINVA: C6A.2(N2) R9A.2(N2) U2A.3
UNNAMED_1_ADA4898_I40_NINVB: C6B.2(N2) R9B.2(N2) U2B.3
UNNAMED_1_ADA4898_I40_NINVC: C6C.2(N2) R9C.2(N2) U2C.3
UNNAMED_1_ADA4898_I40_NINVD: C6D.2(N2) R9D.2(N2) U2D.3
UNNAMED_1_ADA4898_I40_PDNA: R12A.2(N2) U2A.8
UNNAMED_1_ADA4898_I40_PDNB: R12B.2(N2) U2B.8
UNNAMED_1_ADA4898_I40_PDNC: R12C.2(N2) U2C.8
UNNAMED_1_ADA4898_I40_PDND: R12D.2(N2) U2D.8
UNNAMED_1_ADG5421F_I60_D1A: R2A.2(N2) R4A.1 R10A.1 U1A.10
UNNAMED_1_ADG5421F_I60_D1B: R2B.2(N2) R4B.1 R10B.1 U1B.10
UNNAMED_1_ADG5421F_I60_D1C: R2C.2(N2) R4C.1 R10C.1 U1C.10
UNNAMED_1_ADG5421F_I60_D1D: R2D.2(N2) R4D.1 R10D.1 U1D.10
UNNAMED_1_ADG5421F_I60_D2A: R3A.2(N2) R5A.2(N2) R11A.1 U1A.9
UNNAMED_1_ADG5421F_I60_D2B: R3B.2(N2) R5B.2(N2) R11B.1 U1B.9
UNNAMED_1_ADG5421F_I60_D2C: R3C.2(N2) R5C.2(N2) R11C.1 U1C.9
UNNAMED_1_ADG5421F_I60_D2D: R3D.2(N2) R5D.2(N2) R11D.1 U1D.9
UNNAMED_1_CAP_I16_N2A: C15A.2(N2) C17A.2(N2) R16A.1 R18A.2(N2) R19A.2(N2)
UNNAMED_1_CAP_I16_N2B: C15B.2(N2) C17B.2(N2) R16B.1 R18B.2(N2) R19B.2(N2)
UNNAMED_1_CAP_I16_N2C: C15C.2(N2) C17C.2(N2) R16C.1 R18C.2(N2) R19C.2(N2)
UNNAMED_1_CAP_I16_N2D: C15D.2(N2) C17D.2(N2) R16D.1 R18D.2(N2) R19D.2(N2)
UNNAMED_1_CAP_I17_N1A: C16A.1 C17A.1 R17A.1 R20A.2(N2) R21A.2(N2)
UNNAMED_1_CAP_I17_N1B: C16B.1 C17B.1 R17B.1 R20B.2(N2) R21B.2(N2)
UNNAMED_1_CAP_I17_N1C: C16C.1 C17C.1 R17C.1 R20C.2(N2) R21C.2(N2)
UNNAMED_1_CAP_I17_N1D: C16D.1 C17D.1 R17D.1 R20D.2(N2) R21D.2(N2)
UNNAMED_1_CAP_I50_N2A: C3A.2(N2) R4A.2(N2) R6A.2(N2) R8A.1
UNNAMED_1_CAP_I50_N2B: C3B.2(N2) R4B.2(N2) R6B.2(N2) R8B.1
UNNAMED_1_CAP_I50_N2C: C3C.2(N2) R4C.2(N2) R6C.2(N2) R8C.1
UNNAMED_1_CAP_I50_N2D: C3D.2(N2) R4D.2(N2) R6D.2(N2) R8D.1
UNNAMED_1_CAP_I55_N2A: C4A.2(N2) R5A.1 R7A.2(N2) R9A.1
UNNAMED_1_CAP_I55_N2B: C4B.2(N2) R5B.1 R7B.2(N2) R9B.1
UNNAMED_1_CAP_I55_N2C: C4C.2(N2) R5C.1 R7C.2(N2) R9C.1
UNNAMED_1_CAP_I55_N2D: C4D.2(N2) R5D.1 R7D.2(N2) R9D.1
UNNAMED_1_RES_I12_N1A: R10A.2(N2) R14A.1 R16A.2(N2)
UNNAMED_1_RES_I12_N1B: R10B.2(N2) R14B.1 R16B.2(N2)
UNNAMED_1_RES_I12_N1C: R10C.2(N2) R14C.1 R16C.2(N2)
UNNAMED_1_RES_I12_N1D: R10D.2(N2) R14D.1 R16D.2(N2)
UNNAMED_1_RES_I18_N2A: R11A.2(N2) R15A.2(N2) R17A.2(N2)
UNNAMED_1_RES_I18_N2B: R11B.2(N2) R15B.2(N2) R17B.2(N2)
UNNAMED_1_RES_I18_N2C: R11C.2(N2) R15C.2(N2) R17C.2(N2)
UNNAMED_1_RES_I18_N2D: R11D.2(N2) R15D.2(N2) R17D.2(N2)
UNNAMED_12_DIOLED_I371_P: DS1.A(P) R1.2(N2)
UNNAMED_12_ICM24CXX_I354_E0: R3.2(N2) R4.2(N2) U1.1
UNNAMED_12_ICM24CXX_I354_E1: R5.2(N2) R6.2(N2) U1.2
UNNAMED_12_ICM24CXX_I354_E2: R7.2(N2) R8.2(N2) U1.3
UNNAMED_21_ADG5421F_I1_S1: J11.1 R24.1 U3.1
UNNAMED_21_ADG5421F_I1_S2: J12.1 R26.1 U3.2
UNNAMED_21_ADG5421F_I24_S1: J9.1 R23.1 U2.1
UNNAMED_21_ADG5421F_I24_S2: J10.1 R25.1 U2.2
VADJ: P1.D15 P1.D16 P1.D17 P1.D18
VIO: P1.C1 P1.C2 R1A.2(N2) R1B.2(N2) R1C.2(N2) R1D.2(N2) R2.1 R21.2(N2) R22.2(N2)

Pads without a net: U2A 1 5; U2B 1 5; U2C 1 5; U2D 1 5; U3A 1 5; U3B 1 5; U3C 1 5; U3D 1 5

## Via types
v1: diameter 0.406, hole 0.203, TOP to BOTTOM, 195 vias
v2: diameter 0.508, hole 0.254, TOP to BOTTOM, 140 vias

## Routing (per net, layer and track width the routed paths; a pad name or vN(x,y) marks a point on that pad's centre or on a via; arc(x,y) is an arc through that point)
3V3_EEPROM: length 59.1
  TOP w0.2: P1.C12 v1(82.33,37.57) ; P1.C13 v1(82.33,36.94)
  LAYER_4 w0.4: v1(82.33,36.94) 83.06,36.94 83.12,37 ; 83.12,37.5 83.05,37.57 v1(82.33,37.57)
  LAYER_4 w0.6: 83.12,37.5 83.12,32.75 82.3,31.93 79.8,31.93 75.5,27.62 75.5,17.48 74.9,16.88 71.5,16.88 70.55,15.93 v2(70.55,15.2) 71.91,13.85 v2(71.91,9.66) 70.25,8 v2(70.25,1.73) 69.49,0.97 68.76,0.97 v2(68,1.73) 67.24,2.49 66.51,2.49 v2(65.75,1.73)
  BOTTOM w0.4: U1.8 v2(71.91,9.66) ; R5.1 v2(68,1.73) ; C1.2 v2(70.55,15.2) ; R7.1 v2(65.75,1.73) ; R3.1 v2(70.25,1.73)
+12V: length 118.2
  TOP w0.2: P1.B2 v1(81.67,43.92) ; P1.B4 v1(81.67,42.65) ; P1.B1 v1(81.67,44.56) ; P1.B3 v1(81.67,43.29)
  TOP w0.4: R1.1 v2(73.75,47.12)
  LAYER_4 w0.4: v1(81.67,44.56) 75.6,44.56
  LAYER_4 w0.6: v2(61.8,51) 62.05,50.75 62.05,47.12 ; 62.05,47.12 v2(62.05,44.5) 61.8,44.25 v2(61.8,39) 62.05,38.75 v2(62.05,32.5) 62.05,27.25 v2(61.8,27) 62.05,26.75 v2(62.05,20.5) 62.12,20.42 62.12,19.5 61.8,19.17 v2(61.8,15) 62.05,14.75 v2(62.05,8.5) ; 62.05,47.12 v2(73.75,47.12) 75,45.88 75,45.16 75.6,44.56
  BOTTOM w0.4: R12D.1 62.13,12.57 C9D.2 ; R13A.1 62.13,41.5 61.45,42.18 C10A.2 ; U3D.7 60.21,6.87 60.58,6.5 C10D.2 ; U3C.7 60.21,18.87 60.58,18.5 C9C.2 ; C10D.2 61.45,6.18 62.13,5.5 R13D.1 ; C10D.2 61.45,7.9 v2(62.05,8.5) ; v2(62.05,32.5) 61.45,31.9 C10B.2 ; C9A.2 62.13,48.57 R12A.1 ; C9A.2 61.56,48.87 U2A.7 ; C9A.2 61.7,50.9 v2(61.8,51) ; C9D.2 61.7,14.9 v2(61.8,15) ; C9D.2 61.56,12.87 U2D.7 ; U2B.7 61.56,36.87 C9B.2 ; C10B.2 61.45,30.18 62.13,29.5 R13B.1 ; C10B.2 60.58,30.5 60.21,30.86 U3B.7 ; v2(61.8,39) 61.7,38.9 C9B.2 ; C10A.2 60.58,42.5 60.21,42.87 U3A.7 ; C10A.2 61.45,43.9 v2(62.05,44.5) ; R12B.1 62.13,36.57 C9B.2 ; U2C.7 61.56,24.86 C10C.2 ; v2(62.05,20.5) 61.45,19.9 C9C.2 ; C9C.2 61.45,18.18 62.13,17.5 R13C.1 ; v1(81.67,44.56) v1(81.67,43.92) v1(81.67,43.29) v1(81.67,42.65) ; v2(61.8,27) 61.7,26.9 C10C.2 ; C10C.2 62.13,24.57 R12C.1
+12V-40V: length 1.9
  TOP w0.2: P1.A1 P1.A2 P1.A3 P1.A4
+15V: length 169.7
  TOP w0.2: v2(9.68,16.12) 10.23,16.12 U3.5 ; P1.D1 v1(84.21,44.56) ; P1.D3 v1(84.21,43.29) ; P1.D4 v1(84.21,42.65) ; P1.D2 v1(84.21,43.92)
  TOP w0.25: v2(14.45,41.12) 14.43,41.11 U2.5
  LAYER_3 w0.6: v2(43.88,15.7) 44.63,16.46 44.63,24.1 43.55,25.19 43.55,27.5 v2(43.75,27.7) 44.51,28.46 44.51,32.62 43.55,33.58 43.55,38.17 44.25,38.88 v2(44.25,39.7) 45.01,40.46 45.01,43.87 43.49,45.38 43.49,51.44 v2(43.75,51.7)
  LAYER_4 w0.4: v1(84.21,42.65) v1(84.21,43.29) v1(84.21,43.92) v1(84.21,44.56) 84.21,44.83 84.88,45.5
  LAYER_4 w0.6: v2(43.88,15.7) 43.88,14.94 43.38,14.44 43.38,10.94 42.62,10.19 22.31,10.19 16.38,16.12 11.88,16.12 ; v2(43.75,51.7) 44.55,52.5 46.38,52.5 49,55.12 64.75,55.12 68.75,51.12 76.62,51.12 78.62,49.12 83.25,49.12 84.88,47.5 84.88,45.5 ; 11.88,16.12 11.88,39.88 13.12,41.12 v2(14.45,41.12) ; 11.88,16.12 v2(9.68,16.12)
  BOTTOM w0.25: v2(43.88,15.7) 43.88,14.75 43.61,14.48 U1D.5 ; U1B.5 43.61,38.23 44.25,38.88 v2(44.25,39.7) ; U1C.5 43.61,27.56 v2(43.75,27.7) ; U1A.5 43.61,50.48 43.78,50.66 43.78,51.67 v2(43.75,51.7)
  BOTTOM w0.4: v1(84.21,43.92) v1(84.21,43.29) v1(84.21,42.65)
-12V: length 3.7
  TOP w0.2: P1.B11 v1(81.67,38.21) ; P1.B12 v1(81.67,37.57) ; P1.B10 v1(81.67,38.84) ; P1.B9 v1(81.67,39.48)
  BOTTOM w0.4: v1(81.67,39.48) v1(81.67,38.84) v1(81.67,38.21) v1(81.67,37.57)
  vias: v2(56.75,49.5) v2(56.75,43.5) v2(56.75,37.5) v2(56.75,31.5) v2(56.75,25.5) v2(56.75,19.5) v2(56.75,13.5) v2(56.75,7.5)
-15V: length 185.7
  TOP w0.2: P1.D10 v1(84.21,38.84) ; v2(9.68,14.38) 10.23,14.38 U3.6 ; P1.D9 v1(84.21,39.48) ; P1.D7 v1(84.21,40.75) ; P1.D8 v1(84.21,40.11)
  TOP w0.25: v2(14.45,42.88) 14.43,42.89 U2.6
  LAYER_3 w0.6: v1(84.21,40.11) 85.12,41.03 85.12,46 79,52.12 66.88,52.12 63.88,55.12 48.8,55.12 v2(45.38,51.7) 45.12,51.44 45.12,46.38 46.63,44.87 46.63,40.46 v2(45.88,39.7) 45.25,39.07 45.25,36 46.25,35 46.25,28.62 45.38,27.75 v2(45.38,27.7) 45.12,27.45 45.12,25.12 45.75,24.5 45.75,22.62 46.38,22 46.38,16.38 45.7,15.7 v2(45.5,15.7)
  LAYER_4 w0.6: v2(9.68,14.38) 8.8,15.25 7.12,15.25 1.88,20.5 1.88,39.5 5.25,42.88 v2(14.45,42.88) 15.45,43.88 16.88,43.88 27,33.75 42.38,33.75 45.06,36.44 45.06,38.89 v2(45.88,39.7) ; v2(45.38,51.7) 45.37,51.7
  BOTTOM w0.25: U1D.6 45.39,15.59 v2(45.5,15.7) ; v2(45.38,51.7) 45.39,51.68 U1A.6 ; v2(45.38,27.7) 45.39,27.68 U1C.6 ; U1B.6 45.39,38.39 45.88,38.88 v2(45.88,39.7)
  BOTTOM w0.4: v1(84.21,40.75) v1(84.21,40.11) v1(84.21,39.48) v1(84.21,38.84)
3P3V: length 11.7
  TOP w0.2: P1.A12 v1(79.79,37.57) ; P1.A9 v1(79.79,39.48) ; P1.A10 v1(79.79,38.84) ; P1.A11 v1(79.79,38.21)
  TOP w0.4: v1(79.79,37.57) v1(79.79,38.21) v1(79.79,38.84) v1(79.79,39.48) 79.77,39.5 78.75,39.5 76,42.25 76,43.5 75.38,44.12 R2.2
ADC0_IN1N: length 28.7
  TOP w0.2: P1.B19 P1.B20 81.64,32.49 v1(81.8,32.65) ; R24A.2 v1(72.5,40.25) 71.75,40.25 69.5,42.5 69.5,44.12 66.38,47.25 R20A.1
  BOTTOM w0.2: v1(72.5,40.25) 71.75,39.5 71.75,37.25 72.25,36.75 76.5,36.75 77.5,35.75 77.5,34.75 79.6,32.65 v1(81.8,32.65)
ADC0_IN1P: length 24
  TOP w0.2: P1.B18 P1.B17 v1(81.67,34.4) ; R18A.1 66.38,46 68.62,43.75 68.62,42.25 71.88,39 v1(72.75,39) R22A.2
  BOTTOM w0.2: v1(72.75,39) 76,39 78.75,36.25 78.75,35.25 79.6,34.4 v1(81.67,34.4)
ADC0_IN2N: length 29.7
  TOP w0.2: v1(82.33,33.13) P1.C19 P1.C20 ; R25A.2 v1(72.78,41.5) 71.88,41.5 70.38,43 70.38,44.5 66.38,48.5 R21A.1
  BOTTOM w0.2: v1(72.78,41.5) 73.13,41.14 73.13,40.13 72.25,39.25 72.25,39.22 72.24,39.21 72.24,37.45 72.45,37.24 72.99,37.24 72.99,37.25 76.57,37.25 77.9,35.92 77.9,34.92 79.57,33.25 81.92,33.25 82.04,33.13 v1(82.33,33.13)
ADC0_IN2P: length 24.4
  TOP w0.2: P1.C17 P1.C18 v1(82.33,33.76) ; R23A.2 v1(72.78,37.75) 71.88,37.75 67.88,41.75 67.88,43.25 66.38,44.75 R19A.1
  BOTTOM w0.2: v1(72.78,37.75) 76.64,37.75 78.31,36.08 78.31,35.08 79.63,33.76 v1(82.33,33.76)
ADC0_OUTN: length 9.5
  TOP w0.2: R22A.1 R23A.1 75.15,37.75 79.77,33.13 P1.A19 P1.A20
ADC0_OUTP: length 11.1
  TOP w0.2: P1.A18 P1.A17 79.6,34.4 77,37 77,38.75 75.5,40.25 R24A.1 R25A.1
ADC1_IN1N: length 23.6
  TOP w0.2: R20B.1 67.62,35.25 68.38,34.5 68.38,30.9 v1(72.78,26.5) R24B.2 ; v1(81.67,26.78) P1.B29 P1.B28
  BOTTOM w0.2: v1(72.78,26.5) 73.28,26.5 73.56,26.78 v1(81.67,26.78)
ADC1_IN1P: length 28.2
  TOP w0.2: R22B.2 v1(72.78,24) 67.12,29.65 67.12,32.38 66.75,32.75 R18B.1 ; v1(81.67,28.05) P1.B27 P1.B26
  BOTTOM w0.2: v1(72.78,24) 73.28,24.51 73.28,25.46 72.99,25.76 72.8,25.76 72.25,26.31 72.25,27.28 72.24,27.29 72.24,27.71 72.25,27.72 72.25,27.85 72.45,28.05 v1(81.67,28.05)
ADC1_IN2N: length 25
  TOP w0.2: P1.C28 P1.C29 v1(82.33,26.78) ; R25B.2 73,27.75 v1(72.75,27.5) 69.12,31.12 69.12,35.12 67.75,36.5 R21B.1
  BOTTOM w0.2: v1(82.33,26.78) 82.33,26.83 81.88,27.28 81.46,27.28 81.42,27.25 73.28,27.25 73.03,27.5 v1(72.75,27.5)
ADC1_IN2P: length 28.9
  TOP w0.2: P1.C26 P1.C27 v1(82.33,28.05) ; R19B.1 67.25,34 67.75,33.5 67.75,30.28 v1(72.78,25.25) R23B.2
  BOTTOM w0.2: v1(82.33,28.05) 82.33,28.1 81.77,28.66 72.28,28.66 71.75,28.12 71.75,26 72.5,25.25 v1(72.78,25.25)
ADC1_OUTN: length 8.3
  TOP w0.2: P1.A28 P1.A29 77.03,26.78 75.5,25.25 R23B.1 R22B.1
ADC1_OUTP: length 7.8
  TOP w0.2: P1.A26 P1.A27 75.55,28.05 75.25,27.75 R25B.1 R24B.1
ADC2_IN1N: length 19.2
  TOP w0.2: R20C.1 70.53,23.25 v1(72.78,21) R24C.2 ; v1(81.67,22.33) P1.B36 P1.B37
  BOTTOM w0.2: v1(81.67,22.33) 74.11,22.33 v1(72.78,21)
ADC2_IN1P: length 25.3
  TOP w0.2: v1(81.67,23.6) P1.B34 P1.B35 ; R22C.2 v1(72.78,18.5) 70.53,20.75 R18C.1
  BOTTOM w0.2: v1(81.67,23.6) 73.6,23.6 73.25,23.25 72.25,23.25 71,22 71,20.28 v1(72.78,18.5)
ADC2_IN2N: length 22.5
  TOP w0.2: R21C.1 70.53,24.5 v1(72.78,22.25) R25C.2 ; P1.C36 P1.C37 v1(82.33,21.7)
  BOTTOM w0.2: v1(82.33,21.7) 74.45,21.7 73.02,20.27 72.48,20.27 72.25,20.5 72.25,21.72 v1(72.78,22.25)
ADC2_IN2P: length 24
  TOP w0.2: P1.C34 P1.C35 82.51,22.97 82.27,22.73 v1(82.26,22.73) ; R19C.1 70.53,22 v1(72.78,19.75) R23C.2
  BOTTOM w0.2: v1(72.78,19.75) 72.27,19.75 71.6,20.42 71.6,21.79 72.57,22.76 73.51,22.76 73.72,22.97 82.02,22.97 v1(82.26,22.73)
ADC2_OUTN: length 8.4
  TOP w0.2: P1.A36 P1.A37 77.45,21.7 75.5,19.75 R23C.1 R22C.1
ADC2_OUTP: length 7.9
  TOP w0.2: P1.A34 P1.A35 76.47,22.97 75.75,22.25 R25C.1 R24C.1
ADC3_IN1N: length 20.6
  TOP w0.2: P1.B41 P1.B42 v1(81.67,18.52) ; R24D.2 v1(72.9,14.25) 71.9,13.25 68.38,13.25 66.38,11.25 R20D.1
  BOTTOM w0.2: v1(81.67,18.52) 77.18,18.52 v1(72.9,14.25)
ADC3_IN1P: length 26.3
  TOP w0.2: R22D.2 v1(72.9,11.75) 69.25,11.75 66.25,8.75 R18D.1 ; P1.B39 P1.B40 v1(81.67,19.79)
  BOTTOM w0.2: v1(72.9,11.75) 73.41,12.26 73.41,13.54 73.21,13.74 72.69,13.74 72.69,13.75 72.5,13.75 72.25,14 72.25,15.75 76.29,19.79 v1(81.67,19.79)
ADC3_IN2N: length 21.2
  TOP w0.2: R25D.2 v1(72.9,15.5) 71.4,14 67.88,14 66.38,12.5 R21D.1 ; P1.C41 P1.C42 v1(82.33,18.52)
  BOTTOM w0.2: v1(72.9,15.5) 76.43,19.03 81.88,19.03 82.33,18.57 v1(82.33,18.52)
ADC3_IN2P: length 26.5
  TOP w0.2: v1(82.33,19.79) P1.C40 P1.C39 ; R19D.1 66.25,10 68.62,12.38 72.28,12.38 v1(72.9,13) R23D.2
  BOTTOM w0.2: v1(82.33,19.79) 82.33,19.84 81.88,20.3 76.05,20.3 71.75,16 71.75,13.65 72.4,13 v1(72.9,13)
ADC3_OUTN: length 10.8
  TOP w0.2: P1.A41 P1.A42 79.52,18.52 76,15 76,13.5 75.5,13 R23D.1 R22D.1
ADC3_OUTP: length 9.4
  TOP w0.2: P1.A39 P1.A40 79.77,19.79 75.48,15.5 R25D.1 R24D.1
CHA_N: length 10.8
  TOP w0.2: J2.1 39.38,52 41.25,50.12 41.25,48.75 42.12,47.88 v1(42.5,47.88) 43.12,47.88 43.5,47.5 R2A.1
  BOTTOM w0.2: v1(42.5,47.88) 42.62,48 U1A.1
CHA_P: length 21.6
  TOP w0.2: R3A.1 v1(42.5,48.62) 42.12,48.62 41.75,49 41.75,50.38 39.5,52.62 38.88,52.62 38,53.5 36.5,53.5 35,52 J1.1
  BOTTOM w0.2: v1(42.5,48.62) 42.63,48.5 U1A.2
CHB_N: length 12.8
  TOP w0.2: R2B.1 43.5,35.5 43.12,35.88 v1(42.5,35.88) 42.12,35.88 41.12,36.88 41.12,40.12 39.25,42 J4.1
  BOTTOM w0.2: v1(42.5,35.88) 42.62,36 U1B.1
CHB_P: length 23.4
  TOP w0.2: J3.1 34.62,42 36,43.38 38.62,43.38 41.62,40.38 41.62,37.12 42.12,36.62 v1(42.5,36.62) R3B.1
  BOTTOM w0.2: U1B.2 42.63,36.5 v1(42.5,36.62)
CHC_N: length 15.1
  TOP w0.2: J6.1 37,22 38.88,23.88 v1(42.5,23.88) 43.12,23.88 43.5,23.5 R2C.1
  BOTTOM w0.2: v1(42.5,23.88) 42.62,24 U1C.1
CHC_P: length 23.3
  TOP w0.2: R3C.1 v1(42.5,24.62) 33,24.62 27,18.62 J5.1
  BOTTOM w0.2: U1C.2 42.63,24.5 v1(42.5,24.62)
CHD_N: length 12.2
  TOP w0.2: R2D.1 43.38,11.5 43,11.88 v1(42.5,11.88) 41.88,11.88 40.62,10.62 39.12,10.62 37,8.5 J8.1
  BOTTOM w0.2: v1(42.5,11.88) 42.62,12 U1D.1
CHD_P: length 22.3
  TOP w0.2: R3D.1 v1(42.5,12.62) 41.5,12.62 40.5,11.62 30.25,11.62 27,8.38 J7.1
  BOTTOM w0.2: v1(42.5,12.62) 42.63,12.5 U1D.2
DAC0: length 88.6
  TOP w0.2: P1.C24 v1(82.33,29.95) ; U2.10 11.75,44.12 v2(11.5,44.38) ; R10.1 R9.1 R11.1 v1(72.78,32.25) 70.25,34.78 70.25,35.75 65.18,40.82 51.18,40.82 50.19,41.81 47.46,41.81 43.26,46 19,46 18.25,45.25 13,45.25 TP1.1
  BOTTOM w0.2: TP1.1 v2(11.5,44.38) R23.2 ; v1(82.33,29.95) 82.33,30 81.83,30.5 78,30.5 75.5,33 73.53,33 v1(72.78,32.25)
DAC0_RFB0: length 11
  TOP w0.2: R9.2 v1(75.22,31) ; P1.D24 v1(84.21,29.95)
  BOTTOM w0.2: v1(84.21,29.95) 83.45,29.95 82.95,29.45 76.78,29.45 v1(75.22,31)
DAC0_RFB0_X1: length 5.8
  TOP w0.2: R10.2 75.75,29.75 75.95,29.95 P1.A24
DAC0_RFB0_X2: length 8.6
  TOP w0.2: R11.2 v1(75.22,32.25) ; P1.B24 v1(81.67,29.95)
  BOTTOM w0.2: v1(75.22,32.25) 77.52,29.95 v1(81.67,29.95)
DAC1: length 86
  TOP w0.2: R13.1 R12.1 71.75,36 66.12,41.62 51.38,41.62 50.5,42.5 47.89,42.5 43.76,46.62 41.37,46.62 40.75,47.25 18,47.25 17.5,46.75 TP2.1 ; R13.1 v1(72.75,34.75) ; R13.1 R14.1 ; U2.9 12.25,43.87 v2(12.75,44.38) ; P1.C22 v1(82.33,31.22)
  BOTTOM w0.2: TP2.1 14.5,46.75 12.75,45 v2(12.75,44.38) R25.2 ; v1(72.75,34.75) 73.49,35.49 75.51,35.49 75.73,35.27 75.73,34.27 78.27,31.73 81.88,31.73 82.33,31.27 v1(82.33,31.22)
DAC1_RFB1: length 12.7
  TOP w0.2: R12.2 v1(75.22,36) ; P1.D22 v1(84.21,31.22)
  BOTTOM w0.2: v1(84.21,31.22) 83.53,31.22 82.62,32.13 78.62,32.13 76.5,34.25 76.5,35.23 75.73,36 v1(75.22,36)
DAC1_RFB1_X1: length 6.7
  TOP w0.2: P1.A22 77.78,31.22 75.5,33.5 R14.2
DAC1_RFB1_X2: length 9.4
  TOP w0.2: R13.2 v1(75.22,34.75) ; P1.B22 v1(81.67,31.22)
  BOTTOM w0.2: v1(75.22,34.75) 75.22,34.21 78.21,31.22 v1(81.67,31.22)
DAC2: length 97
  TOP w0.2: TP3.1 12.25,7.62 19.12,0.75 45.25,0.75 47.25,2.75 68.5,2.75 71.75,6 R15.1 R17.1 R16.1 v1(72.9,3.5) ; P1.D47 v1(84.21,15.35) ; U3.10 12.25,13.45 12.45,13.25 v1(12.5,13.25)
  BOTTOM w0.2: v1(72.9,3.5) 73.41,2.99 75.49,2.99 83.25,10.75 83.25,15.15 83.45,15.35 v1(84.21,15.35) ; TP3.1 12.25,9.5 12.5,9.75 v1(12.5,13.25) R24.2
DAC2_RFB0: length 15.6
  TOP w0.2: P1.B46 v1(81.67,15.98) ; R15.2 75.1,6 76.75,7.65 v1(76.75,9.12)
  BOTTOM w0.2: v1(81.67,15.98) 78.48,15.98 76.75,14.25 v1(76.75,9.12)
DAC2_RFB0_X1: length 16.2
  TOP w0.2: v1(77.5,9.5) 77.5,7.15 75.1,4.75 R17.2 ; P1.B47 v1(81.67,15.35)
  BOTTOM w0.2: v1(81.67,15.35) 78.6,15.35 77.5,14.25 v1(77.5,9.5)
DAC2_RFB0_X2: length 17.7
  TOP w0.2: P1.C47 v1(82.33,15.35) ; v1(78.25,10) 78.25,6.65 75.1,3.5 R16.2
  BOTTOM w0.2: v1(78.25,10) 78.25,14.25 78.75,14.75 81.78,14.75 82.33,15.3 v1(82.33,15.35)
DAC3: length 92.7
  TOP w0.2: v1(11.62,13.38) 11.75,13.5 U3.9 ; TP4.1 11.5,10.75 20.5,1.75 44.12,1.75 46.12,3.75 67.5,3.75 71,7.25 R18.1 R19.1 R20.1 v1(72.9,9.75) ; P1.C44 v1(82.33,17.25)
  BOTTOM w0.2: R26.2 11.25,13.75 v1(11.62,13.38) 10.5,12.25 TP4.1 ; v1(82.33,17.25) 82.33,17.3 81.88,17.76 78.26,17.76 75.25,14.75 75.25,11.25 73.75,9.75 v1(72.9,9.75)
DAC3_RFB1: length 17.9
  TOP w0.2: P1.D44 v1(84.21,17.25) ; R18.2 75.1,7.25 76.12,8.28 v1(76.12,8.38)
  BOTTOM w0.2: v1(84.21,17.25) 83.5,17.25 82.75,16.5 78.25,16.5 76.25,14.5 76.25,10.5 76.12,10.38 v1(76.12,8.38)
DAC3_RFB1_X1: length 11.2
  TOP w0.2: R20.2 76,9.75 77.25,11 77.25,15 79.5,17.25 P1.A44
DAC3_RFB1_X2: length 14.5
  TOP w0.2: v1(75.49,8.89) 75.1,8.5 R19.2 ; P1.B44 v1(81.67,17.25)
  BOTTOM w0.2: v1(81.67,17.25) 78.32,17.25 75.75,14.68 75.75,10.75 75.49,10.49 v1(75.49,8.89)
GPIO0_VIO: length 86.9
  TOP w0.2: U2.8 12.75,43.5 13.5,44.25 v1(13.88,44.25) ; P1.A31 v1(79.79,25.51)
  LAYER_3 w0.2: v1(79.79,25.51) 77.37,25.51 68.25,34.62 68.25,42.75 64.38,46.62 51.62,46.62 48.75,49.5 v1(46,49.5)
  BOTTOM w0.2: U1A.7 v1(46,49.5) 46,49 U1A.8 44.75,49 44.5,48.75 44.5,47.5 44.12,47.12 20.88,47.12 18,44.25 v1(13.88,44.25)
GPIO1_VIO: length 86.4
  TOP w0.2: U2.7 13.25,43.38 13.62,43.74 14.08,43.74 14.09,43.75 v1(18.75,43.75) ; P1.B31 v1(81.67,25.51)
  LAYER_3 w0.2: v1(46,37.5) 49.25,37.5 52.25,34.5 64.62,34.5 67.88,31.25 67.88,26.75 71.25,23.38 80,23.38 80.75,24.12 80.75,25.12 81.13,25.51 v1(81.67,25.51)
  BOTTOM w0.2: v1(18.75,43.75) 18.75,41.88 23.88,36.75 40.25,36.75 41.75,35.25 44,35.25 44.5,35.75 44.5,36.62 44.88,37 U1B.8 46,37 v1(46,37.5) U1B.7
GPIO2_VIO: length 87.5
  TOP w0.2: v1(14.75,12.5) 11.62,12.5 11.12,13.01 11.12,13.58 11.25,13.72 U3.8 ; P1.C31 v1(82.33,25.51)
  LAYER_3 w0.2: v1(46,25.5) 50.37,25.5 54.25,21.62 74.25,21.62 74.75,22.12 80,22.12 80.97,23.1 81.91,23.1 82.84,24.03 82.84,25.16 82.49,25.51 v1(82.33,25.51)
  BOTTOM w0.2: v1(14.75,12.5) 15.38,12.5 21.5,18.62 21.5,19.38 27.62,25.5 39.12,25.5 41.62,23 43.75,23 44.5,23.75 44.5,24.62 44.88,25 U1C.8 46,25 v1(46,25.5) U1C.7
GPIO3_VIO: length 86.7
  TOP w0.2: U3.7 10.72,14.32 10.72,12.66 11.38,11.99 14.01,11.99 v1(14.5,11.5) ; P1.D31 v1(84.21,25.51)
  LAYER_3 w0.2: v1(46,13.5) 49.5,13.5 52.88,16.88 74.12,16.88 77.62,20.38 83,20.38 83.62,21 83.62,25.12 84.01,25.51 v1(84.21,25.51)
  BOTTOM w0.2: v1(14.5,11.5) 40.38,11.5 41.25,10.62 43.75,10.62 44.5,11.38 44.5,12.62 44.88,13 U1D.8 46,13 v1(46,13.5) U1D.7
GPIO4_VIO: length 183.8
  TOP w0.2: v2(14.4,39.5) 13.25,39.5 12.75,40 U2.3 ; P1.D42 v1(84.21,18.52)
  LAYER_3 w0.2: v2(42.62,39.65) 42.02,39.65 39.87,37.5 24,37.5 21.25,40.25 15.12,40.25 14.4,39.53 v2(14.4,39.5) 4.75,39.5 2.38,37.12 2.38,14.62 15.75,1.25 58.59,1.25 69.38,12.04 69.38,12.18 69.58,12.38 73.5,12.38 79.12,18 83.6,18 84.12,18.52 v1(84.21,18.52)
  LAYER_4 w0.2: v2(42.12,51.65) 42.12,51.5 41.62,51 41.62,40.65 v2(42.62,39.65)
  BOTTOM w0.2: U1A.3 42.88,49 42.12,49.75 v2(42.12,51.65) ; U1B.3 43,37 42.62,37.38 v2(42.62,39.65)
GPIO5_VIO: length 108
  TOP w0.2: v2(9.72,17.75) 10.75,17.75 11.25,17.25 U3.3 ; P1.D41 v1(84.21,19.16)
  LAYER_3 w0.2: v1(84.21,19.16) 77.41,19.16 74.5,16.25 53.62,16.25 49.5,12.12 44.38,12.12 42.25,14.25 v2(42.25,15.65) ; v2(42.25,15.65) 39.4,15.65 34.5,10.75 19.12,10.75 12.12,17.75 v2(9.72,17.75) ; v2(42.25,15.65) 43.12,16.53 43.12,21.12 41.88,22.38 41.88,25.55 42.08,25.75 42.08,27.6 v2(42.12,27.65)
  BOTTOM w0.2: U1C.3 43.12,25 42.12,26 v2(42.12,27.65) ; v2(42.25,15.65) 42.25,13.75 43,13 U1D.3
GPIO7_VIO: length 0.5
  TOP w0.2: P1.C49 v1(82.33,14.08)
GROUND: length 621.9
  TOP w0.2: P1.C9 v1(82.33,39.48) ; P1.A43 P1.B43 P1.C43 P1.D43 v1(84.21,17.89) ; P1.A38 v1(79.79,21.06) ; P1.B16 v1(81.67,35.03) ; P1.D29 v1(84.21,26.78) ; P1.C32 v1(82.33,24.87) ; P1.D27 v1(84.21,28.05) ; P1.D19 v1(84.21,33.13) ; P1.B6 v1(81.67,41.38) ; P1.A45 P1.B45 P1.C45 P1.D45 v1(84.21,16.62) ; P1.C8 v1(82.33,40.11) ; P1.A32 v1(79.79,24.87) ; P1.D20 v1(84.21,32.49) ; P1.D28 v1(84.21,27.41) ; P1.B5 v1(81.67,42.02) ; P1.D12 v1(84.21,37.57) ; P1.B7 v1(81.67,40.75) ; v1(84.21,14.71) P1.D48 P1.C48 P1.B48 P1.A48 ; P1.C30 v1(82.33,26.14) ; P1.D5 v1(84.21,42.02) ; P1.B13 v1(81.67,36.94) ; P1.D32 v1(84.21,24.87) ; P1.D33 v1(84.21,24.24) ; P1.D30 v1(84.21,26.14) ; P1.C6 v1(82.33,41.38) ; P1.D39 v1(84.21,20.43) ; P1.C33 v1(82.33,24.24) ; P1.C50 v1(82.33,13.44) ; P1.B33 v1(81.67,24.24) ; P1.B38 v1(81.67,21.06) ; P1.D14 v1(84.21,36.3) ; P1.B32 v1(81.67,24.87) ; P1.A23 P1.B23 P1.C23 P1.D23 v1(84.21,30.59) ; P1.A21 P1.B21 P1.C21 P1.D21 v1(84.21,31.86) ; P1.A15 v1(79.79,35.67) ; P1.D13 v1(84.21,36.94) ; v1(84.21,29.32) P1.D25 P1.C25 P1.B25 P1.A25 ; U2.4 13.25,40.37 v2(13.38,40.25) ; P1.A7 v1(79.79,40.75) ; P1.A6 v1(79.79,41.38) ; P1.C38 v1(82.33,21.06) ; P1.A13 v1(79.79,36.94) ; P1.C14 v1(82.33,36.3) ; P1.D34 v1(84.21,23.6) ; P1.B14 v1(81.67,36.3) ; P1.C10 v1(82.33,38.84) ; P1.C4 v1(82.33,42.65) ; P1.B30 v1(81.67,26.14) ; P1.D6 v1(84.21,41.38) ; P1.A8 v1(79.79,40.11) ; P1.C7 v1(82.33,40.75) ; P1.A16 v1(79.79,35.03) ; P1.A14 v1(79.79,36.3) ; P1.D11 v1(84.21,38.21) ; P1.B8 v1(81.67,40.11) ; P1.C16 v1(82.33,35.03) ; P1.C3 v1(82.33,43.29) ; P1.A33 v1(79.79,24.24) ; P1.C15 v1(82.33,35.67) ; P1.C11 v1(82.33,38.21) ; P1.D46 v1(84.21,15.98) ; P1.D26 v1(84.21,28.68) ; P1.C5 v1(82.33,42.02) ; P1.D38 v1(84.21,21.06) ; P1.A5 v1(79.79,42.02) ; P1.C46 v1(82.33,15.98) ; P1.A30 v1(79.79,26.14) ; P1.B15 v1(81.67,35.67)
  TOP w0.25: U3.4 10.75,16.75 v2(10.56,16.94) ; P1.D50 v1(84.19,13.44)
  TOP w0.4: v1(50.25,40.5) R7B.1 50.62,40.38 50.95,40.05 51.04,40.05 51.05,40.04 52.62,40.04 C6B.1 ; C6C.1 51.58,28.05 51.25,28.38 R7C.1 v1(50.25,28.5) ; C6D.1 51.58,16.05 51.25,16.38 R7D.1 v1(50.25,16.5) ; v1(50.25,52.5) R7A.1 51.25,52.38 51.58,52.05 C6A.1 ; DS1.C v2(67.91,54.12)
  LAYER_2 w0.2: 8.14,26.29 J12.3 ; J12.3 10.94,26.29 ; J12.3 9.54,27.69 ; J12.3 9.54,24.89 ; J2.5 34.46,50.86 ; J2.5 34.46,48.06 ; J2.5 35.86,49.46 ; J2.5 33.06,49.46 ; 24.46,53.14 J1.2 ; J1.2 25.86,54.54 ; J1.2 24.46,55.94 ; J1.2 23.06,54.54 ; 24.46,43.14 J3.2 ; J3.2 25.86,44.54 ; J3.2 24.46,45.94 ; J3.2 23.06,44.54 ; 8.14,36.54 J9.3 ; J9.3 10.94,36.54 ; J9.3 9.54,35.14 ; J9.3 9.54,37.94 ; 39.54,53.14 J2.3 ; J2.3 38.14,54.54 ; J2.3 39.54,55.94 ; J2.3 40.94,54.54 ; J1.5 24.46,50.86 ; J1.5 25.86,49.46 ; J1.5 23.06,49.46 ; J1.5 24.46,48.06 ; 33.06,8.54 J8.2 ; J8.2 35.86,8.54 ; J8.2 34.46,9.94 ; J8.2 34.46,7.14 ; 38.14,8.54 J8.3 ; J8.3 39.54,7.14 ; J8.3 39.54,9.94 ; J8.3 40.94,8.54 ; 29.54,2.06 J7.4 ; J7.4 30.94,3.46 ; J7.4 29.54,4.86 ; J7.4 28.14,3.46 ; J12.5 5.86,21.21 ; J12.5 4.46,19.81 ; J12.5 4.46,22.61 ; J12.5 3.06,21.21 ; J6.2 34.46,19.94 ; J6.2 35.86,18.54 ; J6.2 33.06,18.54 ; J6.2 34.46,17.14 ; 29.54,12.06 J5.4 ; J5.4 30.94,13.46 ; J5.4 29.54,14.86 ; J5.4 28.14,13.46 ; J5.5 25.86,13.46 ; J5.5 23.06,13.46 ; J5.5 24.46,12.06 ; J5.5 24.46,14.86 ; 3.06,26.29 J12.2 ; J12.2 5.86,26.29 ; J12.2 4.46,24.89 ; J12.2 4.46,27.69 ; J7.5 25.86,3.46 ; J7.5 23.06,3.46 ; J7.5 24.46,4.86 ; J7.5 24.46,2.06 ; 3.06,36.54 J9.2 ; J9.2 4.46,37.94 ; J9.2 5.86,36.54 ; J9.2 4.46,35.14 ; 34.46,43.14 J4.2 ; J4.2 34.46,45.94 ; J4.2 33.06,44.54 ; J4.2 35.86,44.54 ; J3.5 25.86,39.46 ; J3.5 23.06,39.46 ; J3.5 24.46,40.86 ; J3.5 24.46,38.06 ; 14.46,30.06 J10.5 ; J10.5 14.46,32.86 ; J10.5 13.06,31.46 ; J10.5 15.86,31.46 ; J11.3 19.54,27.69 ; J11.3 19.54,24.89 ; J11.3 18.14,26.29 ; J11.3 20.94,26.29 ; J6.4 39.54,14.86 ; J6.4 40.94,13.46 ; J6.4 38.14,13.46 ; J6.4 39.54,12.06 ; 38.14,18.54 J6.3 ; J6.3 40.94,18.54 ; J6.3 39.54,19.94 ; J6.3 39.54,17.14 ; J11.2 15.86,26.29 ; J11.2 14.46,24.89 ; J11.2 14.46,27.69 ; J11.2 13.06,26.29 ; J2.2 34.46,55.94 ; J2.2 34.46,53.14 ; J2.2 35.86,54.54 ; J2.2 33.06,54.54 ; 34.46,12.06 J6.5 ; J6.5 33.06,13.46 ; J6.5 35.86,13.46 ; J6.5 34.46,14.86 ; J10.3 20.94,36.54 ; J10.3 19.54,35.14 ; J10.3 18.14,36.54 ; J10.3 19.54,37.94 ; 19.54,19.81 J11.4 ; J11.4 18.14,21.21 ; J11.4 19.54,22.61 ; J11.4 20.94,21.21 ; J5.3 30.94,18.54 ; J5.3 29.54,19.94 ; J5.3 29.54,17.14 ; J5.3 28.14,18.54 ; 38.14,39.46 J4.4 ; J4.4 39.54,40.86 ; J4.4 40.94,39.46 ; J4.4 39.54,38.06 ; J11.5 14.46,22.61 ; J11.5 15.86,21.21 ; J11.5 14.46,19.81 ; J11.5 13.06,21.21 ; J7.2 25.86,8.54 ; J7.2 24.46,9.94 ; J7.2 24.46,7.14 ; J7.2 23.06,8.54 ; J3.4 30.94,39.46 ; J3.4 28.14,39.46 ; J3.4 29.54,38.06 ; J3.4 29.54,40.86 ; J7.3 29.54,9.94 ; J7.3 28.14,8.54 ; J7.3 30.94,8.54 ; J7.3 29.54,7.14 ; J5.2 24.46,19.94 ; J5.2 23.06,18.54 ; J5.2 24.46,17.14 ; J5.2 25.86,18.54 ; 38.14,44.54 J4.3 ; J4.3 40.94,44.54 ; J4.3 39.54,45.94 ; J4.3 39.54,43.14 ; 39.54,2.06 J8.4 ; J8.4 38.14,3.46 ; J8.4 39.54,4.86 ; J8.4 40.94,3.46 ; J1.4 29.54,50.86 ; J1.4 28.14,49.46 ; J1.4 30.94,49.46 ; J1.4 29.54,48.06 ; 34.46,38.06 J4.5 ; J4.5 35.86,39.46 ; J4.5 33.06,39.46 ; J4.5 34.46,40.86 ; J12.4 9.54,22.61 ; J12.4 9.54,19.81 ; J12.4 10.94,21.21 ; J12.4 8.14,21.21 ; J9.5 5.86,31.46 ; J9.5 4.46,32.86 ; J9.5 4.46,30.06 ; J9.5 3.06,31.46 ; 14.46,35.14 J10.2 ; J10.2 15.86,36.54 ; J10.2 13.06,36.54 ; J10.2 14.46,37.94 ; 39.54,48.06 J2.4 ; J2.4 39.54,50.86 ; J2.4 38.14,49.46 ; J2.4 40.94,49.46 ; J3.3 29.54,45.94 ; J3.3 28.14,44.54 ; J3.3 30.94,44.54 ; J3.3 29.54,43.14 ; 29.54,53.14 J1.3 ; J1.3 30.94,54.54 ; J1.3 29.54,55.94 ; J1.3 28.14,54.54 ; 9.54,30.06 J9.4 ; J9.4 8.14,31.46 ; J9.4 9.54,32.86 ; J9.4 10.94,31.46 ; 18.14,31.46 J10.4 ; J10.4 19.54,32.86 ; J10.4 19.54,30.06 ; J10.4 20.94,31.46 ; J8.5 34.46,4.86 ; J8.5 35.86,3.46 ; J8.5 33.06,3.46 ; J8.5 34.46,2.06
  LAYER_5 w0.2: 28.14,3.46 J7.4 ; J7.4 29.54,4.86 ; J7.4 30.94,3.46 ; J7.4 29.54,2.06 ; 33.06,3.46 J8.5 ; J8.5 35.86,3.46 ; J8.5 34.46,2.06 ; J8.5 34.46,4.86 ; J2.4 39.54,50.86 ; J2.4 38.14,49.46 ; J2.4 40.94,49.46 ; J2.4 39.54,48.06 ; 23.06,3.46 J7.5 ; J7.5 24.46,2.06 ; J7.5 24.46,4.86 ; J7.5 25.86,3.46 ; 24.46,38.06 J3.5 ; J3.5 25.86,39.46 ; J3.5 23.06,39.46 ; J3.5 24.46,40.86 ; 38.14,8.54 J8.3 ; J8.3 39.54,7.14 ; J8.3 39.54,9.94 ; J8.3 40.94,8.54 ; 33.06,18.54 J6.2 ; J6.2 34.46,19.94 ; J6.2 34.46,17.14 ; J6.2 35.86,18.54 ; J11.3 20.94,26.29 ; J11.3 19.54,27.69 ; J11.3 19.54,24.89 ; J11.3 18.14,26.29 ; 14.46,30.06 J10.5 ; J10.5 15.86,31.46 ; J10.5 13.06,31.46 ; J10.5 14.46,32.86 ; 24.46,43.14 J3.2 ; J3.2 23.06,44.54 ; J3.2 25.86,44.54 ; J3.2 24.46,45.94 ; J1.4 29.54,50.86 ; J1.4 30.94,49.46 ; J1.4 29.54,48.06 ; J1.4 28.14,49.46 ; J2.2 34.46,55.94 ; J2.2 33.06,54.54 ; J2.2 34.46,53.14 ; J2.2 35.86,54.54 ; J12.3 9.54,27.69 ; J12.3 9.54,24.89 ; J12.3 10.94,26.29 ; J12.3 8.14,26.29 ; J7.2 24.46,9.94 ; J7.2 23.06,8.54 ; J7.2 25.86,8.54 ; J7.2 24.46,7.14 ; J4.3 40.94,44.54 ; J4.3 39.54,43.14 ; J4.3 39.54,45.94 ; J4.3 38.14,44.54 ; J6.4 40.94,13.46 ; J6.4 38.14,13.46 ; J6.4 39.54,12.06 ; J6.4 39.54,14.86 ; J10.4 20.94,31.46 ; J10.4 19.54,30.06 ; J10.4 18.14,31.46 ; J10.4 19.54,32.86 ; J10.3 20.94,36.54 ; J10.3 18.14,36.54 ; J10.3 19.54,37.94 ; J10.3 19.54,35.14 ; 9.54,19.81 J12.4 ; J12.4 10.94,21.21 ; J12.4 8.14,21.21 ; J12.4 9.54,22.61 ; 19.54,19.81 J11.4 ; J11.4 18.14,21.21 ; J11.4 20.94,21.21 ; J11.4 19.54,22.61 ; J10.2 15.86,36.54 ; J10.2 14.46,35.14 ; J10.2 14.46,37.94 ; J10.2 13.06,36.54 ; J5.3 29.54,19.94 ; J5.3 28.14,18.54 ; J5.3 29.54,17.14 ; J5.3 30.94,18.54 ; 4.46,30.06 J9.5 ; J9.5 5.86,31.46 ; J9.5 4.46,32.86 ; J9.5 3.06,31.46 ; 23.06,49.46 J1.5 ; J1.5 24.46,50.86 ; J1.5 25.86,49.46 ; J1.5 24.46,48.06 ; J2.3 40.94,54.54 ; J2.3 39.54,53.14 ; J2.3 38.14,54.54 ; J2.3 39.54,55.94 ; J9.4 9.54,32.86 ; J9.4 8.14,31.46 ; J9.4 10.94,31.46 ; J9.4 9.54,30.06 ; J11.2 14.46,27.69 ; J11.2 15.86,26.29 ; J11.2 14.46,24.89 ; J11.2 13.06,26.29 ; J4.5 35.86,39.46 ; J4.5 34.46,40.86 ; J4.5 34.46,38.06 ; J4.5 33.06,39.46 ; 24.46,12.06 J5.5 ; J5.5 24.46,14.86 ; J5.5 23.06,13.46 ; J5.5 25.86,13.46 ; J5.4 30.94,13.46 ; J5.4 28.14,13.46 ; J5.4 29.54,14.86 ; J5.4 29.54,12.06 ; 3.06,36.54 J9.2 ; J9.2 5.86,36.54 ; J9.2 4.46,37.94 ; J9.2 4.46,35.14 ; 39.54,17.14 J6.3 ; J6.3 40.94,18.54 ; J6.3 38.14,18.54 ; J6.3 39.54,19.94 ; J3.3 30.94,44.54 ; J3.3 29.54,45.94 ; J3.3 28.14,44.54 ; J3.3 29.54,43.14 ; 38.14,3.46 J8.4 ; J8.4 39.54,4.86 ; J8.4 39.54,2.06 ; J8.4 40.94,3.46 ; J1.3 30.94,54.54 ; J1.3 28.14,54.54 ; J1.3 29.54,53.14 ; J1.3 29.54,55.94 ; 34.46,48.06 J2.5 ; J2.5 34.46,50.86 ; J2.5 35.86,49.46 ; J2.5 33.06,49.46 ; J4.4 39.54,40.86 ; J4.4 39.54,38.06 ; J4.4 38.14,39.46 ; J4.4 40.94,39.46 ; 28.14,39.46 J3.4 ; J3.4 29.54,38.06 ; J3.4 30.94,39.46 ; J3.4 29.54,40.86 ; J7.3 29.54,9.94 ; J7.3 29.54,7.14 ; J7.3 28.14,8.54 ; J7.3 30.94,8.54 ; 34.46,43.14 J4.2 ; J4.2 34.46,45.94 ; J4.2 33.06,44.54 ; J4.2 35.86,44.54 ; J12.5 5.86,21.21 ; J12.5 4.46,19.81 ; J12.5 4.46,22.61 ; J12.5 3.06,21.21 ; J11.5 15.86,21.21 ; J11.5 14.46,19.81 ; J11.5 13.06,21.21 ; J11.5 14.46,22.61 ; J5.2 24.46,19.94 ; J5.2 23.06,18.54 ; J5.2 24.46,17.14 ; J5.2 25.86,18.54 ; J1.2 25.86,54.54 ; J1.2 24.46,53.14 ; J1.2 23.06,54.54 ; J1.2 24.46,55.94 ; 4.46,24.89 J12.2 ; J12.2 4.46,27.69 ; J12.2 5.86,26.29 ; J12.2 3.06,26.29 ; 34.46,12.06 J6.5 ; J6.5 34.46,14.86 ; J6.5 35.86,13.46 ; J6.5 33.06,13.46 ; J8.2 34.46,9.94 ; J8.2 35.86,8.54 ; J8.2 34.46,7.14 ; J8.2 33.06,8.54 ; J9.3 9.54,37.94 ; J9.3 8.14,36.54 ; J9.3 9.54,35.14 ; J9.3 10.94,36.54
  BOTTOM w0.2: U1D.4 v2(44.3,13.5) ; U1C.4 v2(44.3,25.5) ; U1B.4 v2(44.3,37.5)
  BOTTOM w0.25: U1A.4 v2(44.3,49.5)
  BOTTOM w0.4: R4.1 v2(71.38,1.73) ; v1(50.25,28.5) 50.45,28.3 C11C.1 ; C12D.1 50.45,16.3 v1(50.25,16.5) ; v2(50.25,46) 49.95,45.7 C12A.1 ; C11D.1 49.95,9.7 v2(50.25,10) ; R6.1 v2(69.12,1.73) ; C12C.1 49.95,21.7 v2(50.25,22) ; C12B.1 49.95,33.7 v2(50.25,34) ; v1(50.25,52.5) 50.45,52.3 C11A.1 ; C1.1 v2(68.95,15.07) ; U1.7 v2(70.63,9.63) ; v1(50.25,40.5) 50.45,40.3 C11B.1 ; R8.1 v2(66.88,1.73) ; U1.4 v2(68.09,7.6)
  vias: v2(8.07,16.12) v2(8.07,14.38) v2(16.05,42.88) v2(16.05,41.12) v2(43.75,53.3) v2(43.75,29.3) v2(43.88,17.3) v2(44.25,41.3) v2(45.38,53.3) v2(45.38,29.3) v2(45.5,17.3) v2(45.88,41.3) v2(49.8,53.25) v2(49.8,47.25) v2(49.8,41.25) v2(49.8,35.25) v2(49.8,29.25) v2(49.8,23.25) v2(49.8,17.25) v2(49.8,11.25) v2(52.62,45.68) v2(52.62,33.68) v2(52.62,21.68) v2(52.62,9.68) v2(60.75,49.55) v2(60.75,44.2) v2(60.75,37.55) v2(60.75,32.2) v2(60.75,25.55) v2(60.75,20.2) v2(60.75,13.55) v2(60.75,8.2) v2(63.05,42.5) v2(63.05,30.5) v2(63.05,18.5) v2(63.05,6.5) v2(63.3,49) v2(63.3,37) v2(63.3,25) v2(63.3,13) v2(63.7,51) v2(63.7,39) v2(63.7,27) v2(63.7,15) v2(63.95,44.5) v2(63.95,32.5) v2(63.95,20.5) v2(63.95,8.5)
